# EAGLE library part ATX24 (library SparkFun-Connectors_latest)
ATX24 Pin Power Supply Connector - Right Angle PTH Mount This is a good connector for connecting a computer power supply to a PCB. It's massive, but provides many amps of power at 5V and 12V. SparkFun Products: SparkFun Benchtop Power Board Kit SparkFun Power Driver Shield Kit

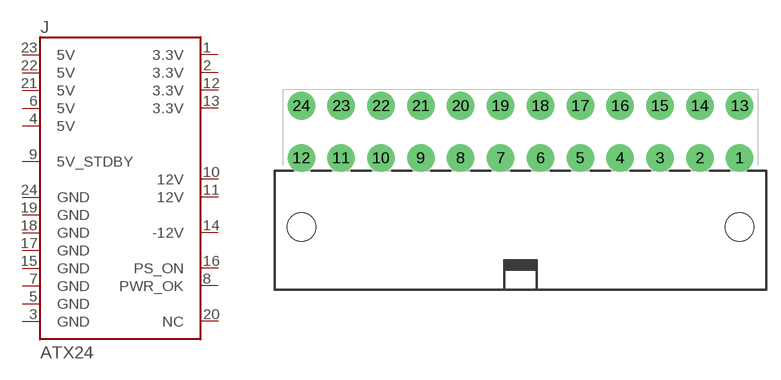
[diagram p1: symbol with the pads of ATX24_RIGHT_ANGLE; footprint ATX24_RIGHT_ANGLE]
Designator prefix J

## ATX24RH (PROD_ID: CONN-09674; SF_ID: PRT-09498)  [ATX24_RIGHT_ANGLE]
1  3.3V
2  3.3V
3  GND
4  5V
5  GND
6  5V
7  GND
8  PWR_OK
9  5V_STDBY
10  12V
11  12V
12  3.3V
13  3.3V
14  -12V
15  GND
16  PS_ON
17  GND
18  GND
19  GND
20  NC
21  5V
22  5V
23  5V
24  GND

## Footprint ATX24_RIGHT_ANGLE (pad centres in mm)
Molex Mini-Fit Jr. - 24 pin, Right Angle Specifications: Pin count:24 Datasheet referenced for footprint Example device(s): ATX24
drill 1.8 pad 2.9: 1 23.1,4.76; 2 18.9,4.76; 3 14.7,4.76; 4 10.5,4.76; 5 6.3,4.76; 6 2.1,4.76; 7 -2.1,4.76; 8 -6.3,4.76; 9 -10.5,4.76; 10 -14.7,4.76; 11 -18.9,4.76; 12 -23.1,4.76; 13 23.1,10.26; 14 18.9,10.26; 15 14.7,10.26; 16 10.5,10.26; 17 6.3,10.26; 18 2.1,10.26; 19 -2.1,10.26; 20 -6.3,10.26; 21 -10.5,10.26; 22 -14.7,10.26; 23 -18.9,10.26; 24 -23.1,10.26
hole 3 at -23.1,-2.54
hole 3 at 23.1,-2.54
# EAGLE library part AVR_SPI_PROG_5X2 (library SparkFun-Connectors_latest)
AVR 10-pin ICSP Header This is the standard AVR In Circuit Serial Programming header. Minimal, but includes pin one indicator. Works with standard Olimex programmers. SparkFun Products: 2x5 AVR ICSP Male Header - PTH 2x5 Pin Shrouded Header - PTH2

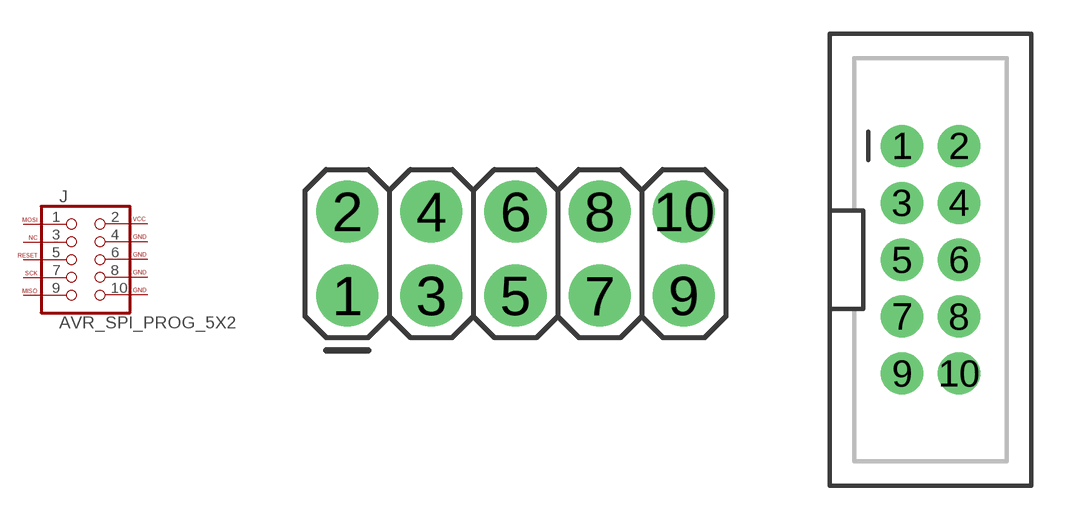
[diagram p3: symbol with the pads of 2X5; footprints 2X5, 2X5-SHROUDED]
Designator prefix J

## AVR_SPI_PROG_5X2PTH  [2X5]
1  MOSI  pas
2  VCC  pwr
3  NC  nc
4  GND  pwr
5  RESET  pas
6  GND  pwr
7  SCK  pas
8  GND  pwr
9  MISO  pas
10  GND  pwr

## AVR_SPI_PROG_5X2PTH2 (PROD_ID: CONN-08671; SF_ID: PRT-08506)  [2X5-SHROUDED]
Pads as for 2X5

## AVR_SPI_PROG_5X2LOCK (PROD_ID: CONN-08671; SF_ID: PRT-08506)  [2X5-SHROUDED_LOCK]
Pads as for 2X5

## AVR_SPI_PROG_5X2SMD  [2X5-SHROUDED_SMD]
Pads as for 2X5

## Footprint 2X5 (pad centres in mm)
Plated Through Hole - 2x5 Specifications: Pin count:10 Pin pitch:0.1" Example device(s): CONN_05x2
drill 1.016 pad 1.88: 1 0,0; 2 0,2.54; 3 2.54,0; 4 2.54,2.54; 5 5.08,0; 6 5.08,2.54; 7 7.62,0; 8 7.62,2.54; 9 10.16,0; 10 10.16,2.54

## Footprint 2X5-SHROUDED (pad centres in mm)
Plated Through Hole - 2x5 Shrouded Header Specifications: Pin count:10 Pin pitch:0.1" Datasheet referenced for footprint Example device(s): CONN_05x2
drill 1.016 pad 1.88: 1 -1.27,5.08; 2 1.27,5.08; 3 -1.27,2.54; 4 1.27,2.54; 5 -1.27,0; 6 1.27,0; 7 -1.27,-2.54; 8 1.27,-2.54; 9 -1.27,-5.08; 10 1.27,-5.08

## Footprint 2X5-SHROUDED_LOCK (pad centres in mm)
Plated Through Hole - 2x5 Shrouded Header Locking Footprint Holes are offset 0.005" from center, to hold pins in place during soldering. Specifications: Pin count:10 Pin pitch:0.1" Datasheet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
drill 1.016 pad 1.88: 1 -1.397,5.08; 2 1.397,5.08; 3 -1.397,2.54; 4 1.397,2.54; 5 -1.397,0; 6 1.397,0; 7 -1.397,-2.54; 8 1.397,-2.54; 9 -1.397,-5.08; 10 1.397,-5.08

## Footprint 2X5-SHROUDED_SMD (pad centres in mm)
Surface Mount - 2x5 Shrouded Header Specifications: Pin count:10 Pin pitch:0.1" Datasheet referenced for footprint Example device(s): CONN_05x2
smd 4.15 x 1: 1 -2.794,5.08; 2 2.794,5.08; 3 -2.794,2.54; 4 2.794,2.54; 5 -2.794,0; 6 2.794,0; 7 -2.794,-2.54; 8 2.794,-2.54; 9 -2.794,-5.08; 10 2.794,-5.08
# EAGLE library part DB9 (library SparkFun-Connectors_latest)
DB9 Connector Standard DB9 (D-Sub 9) serial connector. Can be used for CAN bus as well as RS485 and RS232. Footprint production proven. Here is the female version connector we sell at SparkFun: 9 Pin Female Serial Connector - PCB Mount (PRT-00429) This connector has been used on the following SparkFun products: SparkFun RS232 Shifter - SMD (PRT-00449) SparkFun RS232 Shifter SMD (No DB9) (PRT-08780)

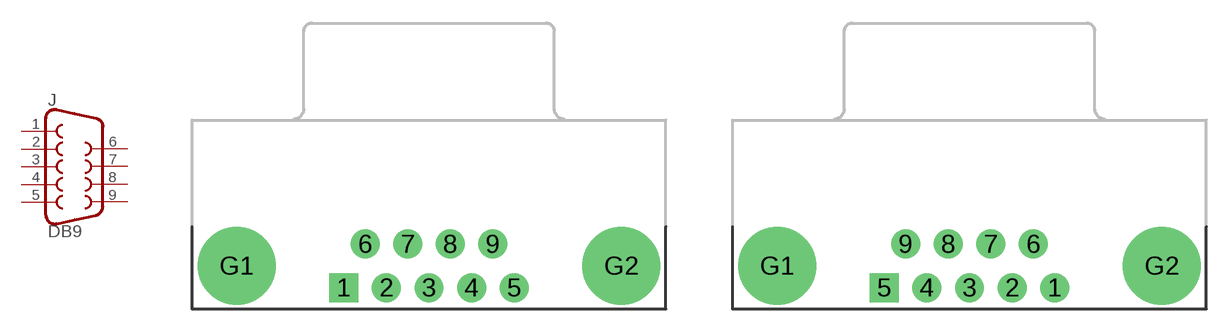
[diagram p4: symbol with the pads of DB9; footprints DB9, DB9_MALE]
Designator prefix J

## DB9FEMALE (PROD_ID: CONN-08194)  [DB9]
1  1  pas
2  2  pas
3  3  pas
4  4  pas
5  5  pas
6  6  pas
7  7  pas
8  8  pas
9  9  pas

## DB9MALE (PROD_ID: CONN-09904)  [DB9_MALE]
Pads as for DB9

## Footprint DB9 (pad centres in mm)
9 Pin Serial Connector - Female PCB Mount Right Angle 0.318" style. Specifications: Pin count:11 Datasheet referenced for footprint Example device(s): DB9
drill 1.016 pad 1.88 square: 1 -5.54,-1.42
drill 1.016 pad 1.88: 2 -2.77,-1.42; 3 0,-1.42; 4 2.77,-1.42; 5 5.54,-1.42; 6 -4.15,1.42; 7 -1.38,1.42; 8 1.38,1.42; 9 4.15,1.42
drill 3.302 pad 5.08: G1 -12.5,0; G2 12.5,0

## Footprint DB9_MALE (pad centres in mm)
9 Pin Serial Connector - Male PCB Mount Right Angle 0.318" style. Specifications: Pin count:11 Datasheet referenced for footprint Example device(s): DB9
drill 1.016 pad 1.88: 1 5.54,-1.42; 2 2.77,-1.42; 3 0,-1.42; 4 -2.77,-1.42; 6 4.15,1.42; 7 1.38,1.42; 8 -1.38,1.42; 9 -4.15,1.42
drill 1.016 pad 1.88 square: 5 -5.54,-1.42
drill 3.302 pad 5.08: G1 -12.5,0; G2 12.5,0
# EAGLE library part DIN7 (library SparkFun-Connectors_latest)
Mini-DIN7 Connector Through-hole MiniDIN 7 connector. Commonly used with Roomba products. Don't confuse this with DIN-6, which is commonly used on oldschool keyboards and mice. Here is the female version connector we sell at SparkFun: MiniDIN 7-Pin Connector (PRT-00696)

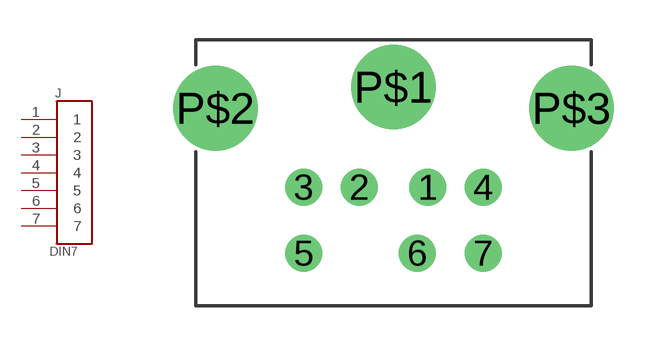
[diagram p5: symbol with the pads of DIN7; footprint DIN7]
Designator prefix J

## DIN7 (PROD_ID: CONN-08318; SF_ID: PRT-00696)  [DIN7]
1  1
2  2
3  3
4  4
5  5
6  6
7  7

## Footprint DIN7 (pad centres in mm)
miniDIN Right Angle Specifications: Pin count:7 Datasheet referenced for footprint Example device(s): DIN7
drill 0.9: 1 1.3,-3.8; 2 -1.3,-3.8; 3 -3.4,-3.8; 4 3.4,-3.8; 5 -3.4,-6.3; 6 0.9,-6.3; 7 3.4,-6.3
drill 2.2: P$1 0,0; P$2 -6.75,-0.8; P$3 6.75,-0.8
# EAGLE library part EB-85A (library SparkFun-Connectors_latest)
EB-85A Connector Horizontal surface mount connector for the EB-85A/FV-M8 GPS receiver. Here is the connector we sell at SparkFun: Connector Horizontal SMD for EB-85A (GPS-08297) Datasheet It was also used on this SparkFun product: This connector is not on any currently live products, however it has been used on previously reitred products, so the package is proven.

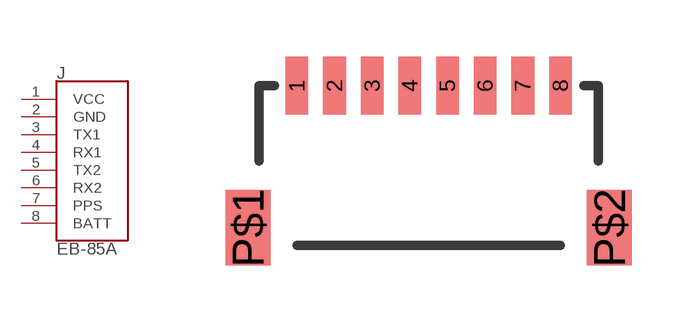
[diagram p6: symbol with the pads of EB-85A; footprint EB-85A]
Designator prefix J

## EB-85ASMD (PROD_ID: CONN-08435; SF_ID: GPS-08297)  [EB-85A]
1  VCC  pwr
2  GND  pwr
3  TX1  out
4  RX1  in
5  TX2  out
6  RX2  in
7  PPS  out
8  BATT  pwr

## Footprint EB-85A (pad centres in mm)
EB-85A Connector Horizontal surface mount connector for the EB-85A/FV-M8 GPS receiver. Specifications: Pin count: 10 Datasheet referenced for footprint Example device(s): EB-85A
smd 0.6 x 1.55: 1 0,0; 2 1,0; 3 2,0; 4 3,0; 5 4,0; 6 5,0; 7 6,0; 8 7,0
smd 1.2 x 2: P$1 -1.3,-3.775; P$2 8.3,-3.775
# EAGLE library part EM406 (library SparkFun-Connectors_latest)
EM406 GPS Connector Here is a six pin vertical 1.0mm pitch connector. It is useful if you need something very tiny as a connection. These are not the standard JST type connectors we use on most of our boards, but are actually the much smaller JST-SH type. Here is the connector we sell at SparkFun: JST SH Vertical 6-Pin Connector - SMD (GPS-00579) Datasheet It was used on these SparkFun products: SparkFun GPS Breakout (BOB-11818) SparkFun Weather Shield (DEV-12081) And many, many other GPS related products.

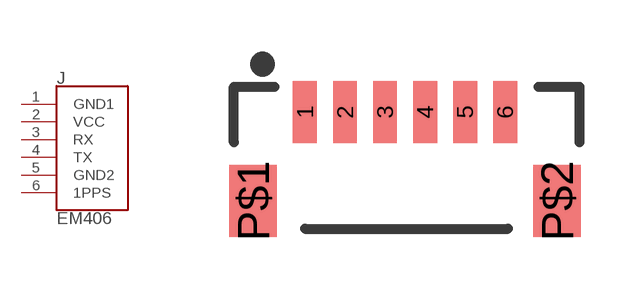
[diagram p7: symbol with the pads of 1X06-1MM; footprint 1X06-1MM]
Designator prefix J

## EM406 (PROD_ID: CONN-08249; SF_ID: GPS-00579)  [1X06-1MM]
1  GND1
2  VCC
3  RX
4  TX
5  GND2
6  1PPS

## Footprint 1X06-1MM (pad centres in mm)
JST SH Vertical 6-Pin Connector -SMD Specifications: Pin count:6 Pin pitch:1mm Datasheet referenced for footprint Example device(s): CONN_06 EM-406
smd 0.6 x 1.55: 1 -2.54,1.27; 2 -1.54,1.27; 3 -0.54,1.27; 4 0.46,1.27; 5 1.46,1.27; 6 2.46,1.27
smd 1.2 x 1.8: P$1 -3.84,-0.955; P$2 3.76,-0.955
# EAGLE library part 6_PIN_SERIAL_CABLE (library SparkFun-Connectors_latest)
6-pin header connection for use with the "FTDI BASIC" pinout - CABLE SIDE. Also known as "Arduino Serial Program Header". This is used on a design to provide a 6-pin connection point for serial communication usually from a USB cable (D+/D-) to these headers (RX/TX). It also has the remaining pins necessary for programming in the Arduino evironment (DTR, GND, and sometimes VCC). Note, this device has "CABLE" in the name. It is intended to be used on a design that usually lives on the end of your USB cable and prvides the converter chip (FTDI232 or FTDI231x) to commnicate serial RX/TX. The "sister" device, named "TARGET" is inteneded to be used on a design that contains a target micro-controller that you wish to program. You can populate with some of these: Female Headers (PRT-00115) For reference (or to suit your programming needs) check out these designs: SparkFun FTDI Basic Breakout - 5V (DEV-09716) SparkFun FTDI Basic Breakout - 3.3V (DEV-09873) SparkFun FTDI SmartBasic (DEV-12935) SparkFun Beefy 3 - FTDI Basic Breakout (DEV-13746)

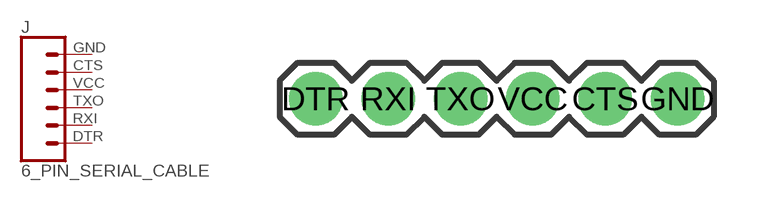
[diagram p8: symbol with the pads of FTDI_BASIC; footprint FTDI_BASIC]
Designator prefix J

## 6_PIN_SERIAL_CABLEPTH  [FTDI_BASIC]
CTS  5  pas
DTR  1  pas
GND  6  pas
RXI  2  pas
TXO  3  pas
VCC  4  pas

## Footprint FTDI_BASIC (pad centres in mm)
FTDI Basic Includes tDocu labels for end pins that match the FTDI Basic connection. Specifications: Pin count: 6 Pin pitch: 0.1" Example device(s): 6_Pin_Serial_Cable
drill 1.016 pad 1.88: CTS 10.16,0; DTR 0,0; GND 12.7,0; RXI 2.54,0; TXO 5.08,0; VCC 7.62,0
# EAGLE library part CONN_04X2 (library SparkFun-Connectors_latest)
Multi connection point. Often used as Generic Header-pin footprint for 0.1 inch spaced/style header connections On any of the 0.1 inch spaced packages, you can populate with these: Break Away Headers - Straight (PRT-00116) Break Away Male Headers - Right Angle (PRT-00553) Female Headers (PRT-00115) Break Away Headers - Machine Pin (PRT-00117) Break Away Female Headers - Swiss Machine Pin (PRT-00743)

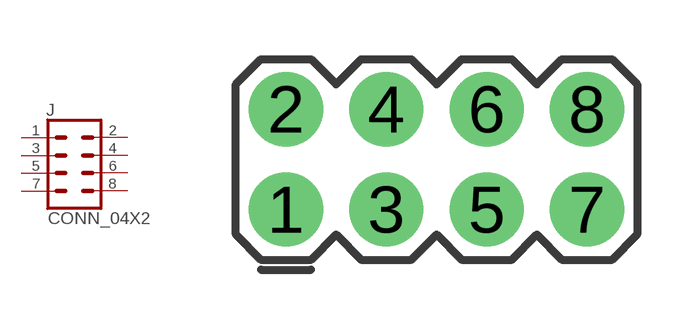
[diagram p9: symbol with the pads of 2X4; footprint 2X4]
Designator prefix J

## CONN_04X2  [2X4]
1  1  pas
2  2  pas
3  3  pas
4  4  pas
5  5  pas
6  6  pas
7  7  pas
8  8  pas

## Footprint 2X4 (pad centres in mm)
Plated Through Hole - 2x4 Specifications: Pin count:8 Pin pitch:0.1" Example device(s): CONN_04x2
drill 1.016 pad 1.88: 1 -3.81,-1.27; 2 -3.81,1.27; 3 -1.27,-1.27; 4 -1.27,1.27; 5 1.27,-1.27; 6 1.27,1.27; 7 3.81,-1.27; 8 3.81,1.27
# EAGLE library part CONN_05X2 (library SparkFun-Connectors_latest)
Multi connection point. Often used as Generic Header-pin footprint for 0.1 inch spaced/style header connections For AVR SPI programming port, see special device with nice symbol: "AVR_SPI_PROG_5x2.dev" You can populate with any combo of single row headers, but if you'd like an exact match, check these: 2x5 AVR ICSP Male Header (PRT-00778) 2x5 Pin Shrouded Header (PRT-08506) On any of the 0.1 inch spaced packages, you can populate with these: Break Away Headers - Straight (PRT-00116) Break Away Male Headers - Right Angle (PRT-00553) Female Headers (PRT-00115) Break Away Headers - Machine Pin (PRT-00117) Break Away Female Headers - Swiss Machine Pin (PRT-00743) Special note: the shrouded connector mates well with our 5x2 ribbon cables: 2x5 Pin IDC Ribbon Cable (PRT-08535)

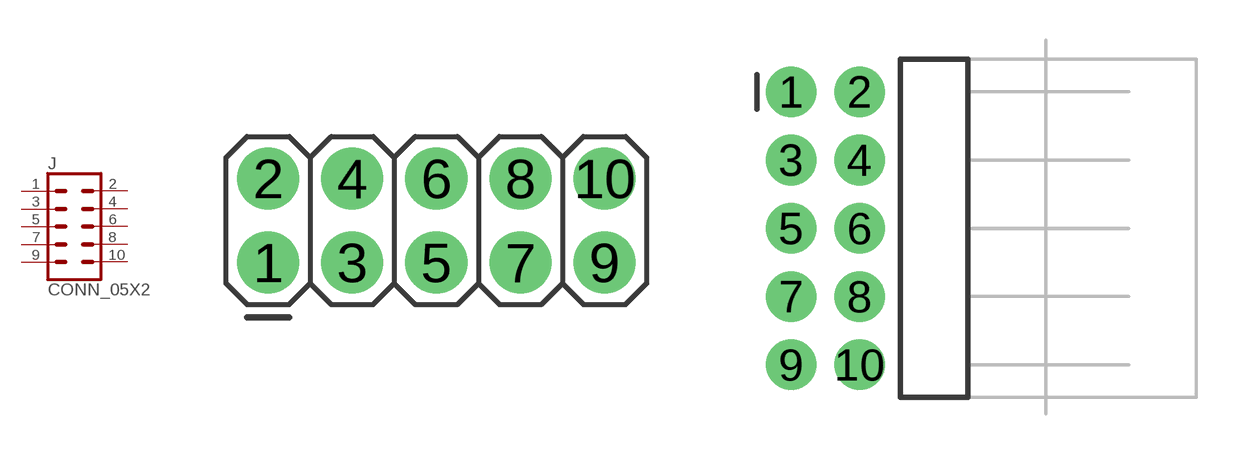
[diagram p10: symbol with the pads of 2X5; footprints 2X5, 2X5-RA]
Designator prefix J

## CONN_05X2PTH (PROD_ID: CONN-08499; SF_ID: PRT-0778)  [2X5]
1  1  pas
2  2  pas
3  3  pas
4  4  pas
5  5  pas
6  6  pas
7  7  pas
8  8  pas
9  9  pas
10  10  pas

## CONN_05X2RA  [2X5-RA]
Pads as for 2X5

## CONN_05X2RAF  [2X5-RAF]
Pads as for 2X5

## CONN_05X2SHD (PROD_ID: CONN-08671; SF_ID: PRT-08506)  [2X5-SHROUDED]
Pads as for 2X5

## CONN_05X2SHD_LOCK (PROD_ID: CONN-08671; SF_ID: PRT-08506)  [2X5-SHROUDED_LOCK]
Pads as for 2X5

## CONN_05X2SHD_SMD (PROD_ID: CONN-09508)  [2X5-SHROUDED_SMD]
Pads as for 2X5

## CONN_05X2NO_SILK  [2X5_NOSILK]
Pads as for 2X5

## CONN_05X20.05_IN_PTH_SILK  [2X5_PTH_SILK_.05]
Pads as for 2X5

## CONN_05X2SHD-NS (PROD_ID: CONN-08671; SF_ID: PRT-08506)  [2X5-SHROUDED-NS]
Pads as for 2X5

## Footprint 2X5 (pad centres in mm)
Plated Through Hole - 2x5 Specifications: Pin count:10 Pin pitch:0.1" Example device(s): CONN_05x2
drill 1.016 pad 1.88: 1 0,0; 2 0,2.54; 3 2.54,0; 4 2.54,2.54; 5 5.08,0; 6 5.08,2.54; 7 7.62,0; 8 7.62,2.54; 9 10.16,0; 10 10.16,2.54

## Footprint 2X5-RA (pad centres in mm)
Plated Through Hole - 2x5 Right Angle Male Headers tDocu shows pin location. Specifications: Pin count:10 Pin pitch:0.1" Example device(s): CONN_05x2
drill 1.016 pad 1.88: 1 -1.27,5.08; 2 1.27,5.08; 3 -1.27,2.54; 4 1.27,2.54; 5 -1.27,0; 6 1.27,0; 7 -1.27,-2.54; 8 1.27,-2.54; 9 -1.27,-5.08; 10 1.27,-5.08

## Footprint 2X5-RAF (pad centres in mm)
Plated Through Hole - 2x5 Right Angle Female Header Silk outline of pins Specifications: Pin count:10 Pin pitch:0.1" Example device(s): CONN_05x2
drill 1.016 pad 1.88: 1 -1.27,5.08; 2 1.27,5.08; 3 -1.27,2.54; 4 1.27,2.54; 5 -1.27,0; 6 1.27,0; 7 -1.27,-2.54; 8 1.27,-2.54; 9 -1.27,-5.08; 10 1.27,-5.08

## Footprint 2X5-SHROUDED (pad centres in mm)
Plated Through Hole - 2x5 Shrouded Header Specifications: Pin count:10 Pin pitch:0.1" Datasheet referenced for footprint Example device(s): CONN_05x2
drill 1.016 pad 1.88: 1 -1.27,5.08; 2 1.27,5.08; 3 -1.27,2.54; 4 1.27,2.54; 5 -1.27,0; 6 1.27,0; 7 -1.27,-2.54; 8 1.27,-2.54; 9 -1.27,-5.08; 10 1.27,-5.08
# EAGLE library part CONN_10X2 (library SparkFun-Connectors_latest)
Multi connection point. Often used as Generic Header-pin footprint for 0.1 inch spaced/style header connections On any of the 0.1 inch spaced packages, you can populate with these: Break Away Headers - Straight (PRT-00116) Break Away Male Headers - Right Angle (PRT-00553) Female Headers (PRT-00115) Break Away Headers - Machine Pin (PRT-00117) Break Away Female Headers - Swiss Machine Pin (PRT-00743) Special note about the "SPECIAL" package: This was SPECIALLY designed to be used with our Graphic LCD Backpack. Be sure you want to use this! It is not only staggered on each line of header holes, but IT IS ALSO offset of the center point of the top and bottom lines by 5 mil. This causes the headers to lock into place on the "standard" footprint on the LCD screen. The extra squares on the tdocu layer are there simply to reference other pins (if you were to actually populate a longer header than ten long - this is what we do with the backpacks).

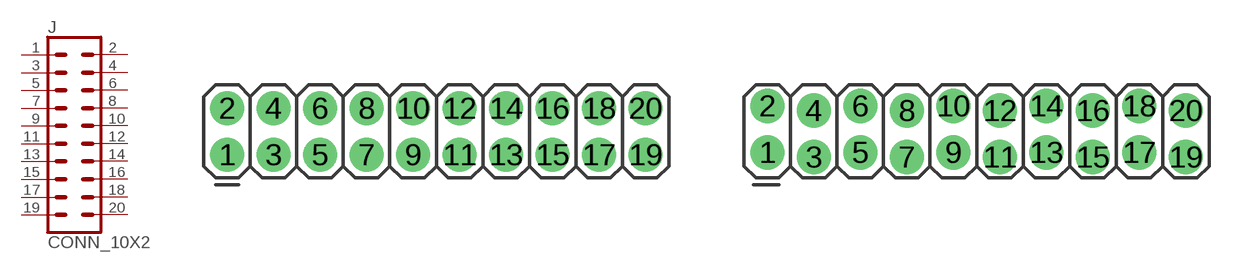
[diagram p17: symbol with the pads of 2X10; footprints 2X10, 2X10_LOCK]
Designator prefix J

## CONN_10X2  [2X10]
1  1  pas
2  2  pas
3  3  pas
4  4  pas
5  5  pas
6  6  pas
7  7  pas
8  8  pas
9  9  pas
10  10  pas
11  11  pas
12  12  pas
13  13  pas
14  14  pas
15  15  pas
16  16  pas
17  17  pas
18  18  pas
19  19  pas
20  20  pas

## CONN_10X22X10_LOCK  [2X10_LOCK]
Pads as for 2X10

## CONN_10X2SPECIAL  [2X10_LOCK_SPECIAL]
Pads as for 2X10

## CONN_10X2NOSILK  [2X10_NOSILK]
Pads as for 2X10

## Footprint 2X10 (pad centres in mm)
Plated Through Hole - 2x10 Specifications: Pin count:20 Pin pitch:0.1" Example device(s): CONN_10x2
drill 1.016 pad 1.88: 1 0,0; 2 0,2.54; 3 2.54,0; 4 2.54,2.54; 5 5.08,0; 6 5.08,2.54; 7 7.62,0; 8 7.62,2.54; 9 10.16,0; 10 10.16,2.54; 11 12.7,0; 12 12.7,2.54; 13 15.24,0; 14 15.24,2.54; 15 17.78,0; 16 17.78,2.54; 17 20.32,0; 18 20.32,2.54; 19 22.86,0; 20 22.86,2.54

## Footprint 2X10_LOCK (pad centres in mm)
Plated Through Hole - 2x10 Locking Footprint Holes are offset 0.005", to hold pins in place while soldering. Specifications: Pin count:20 Pin pitch:0.1" Example device(s): CONN_10x2
drill 1.016 pad 1.88: 1 0,0.127; 2 0,2.667; 3 2.54,-0.127; 4 2.54,2.413; 5 5.08,0.127; 6 5.08,2.667; 7 7.62,-0.127; 8 7.62,2.413; 9 10.16,0.127; 10 10.16,2.667; 11 12.7,-0.127; 12 12.7,2.413; 13 15.24,0.127; 14 15.24,2.667; 15 17.78,-0.127; 16 17.78,2.413; 17 20.32,0.127; 18 20.32,2.667; 19 22.86,-0.127; 20 22.86,2.413

## Footprint 2X10_LOCK_SPECIAL (pad centres in mm)
Plated Through Hole - 2x10 Locking Footprint Special Holes are offset 0.005", to hold pins in place while soldering. Pin rows are offset 5mm as well Specifications: Pin count:20 Pin pitch:0.1"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
drill 1.016 pad 1.88: 1 0,-0.152; 2 0,2.946; 3 2.54,-0.406; 4 2.54,2.692; 5 5.08,-0.152; 6 5.08,2.946; 7 7.62,-0.406; 8 7.62,2.692; 9 10.16,-0.152; 10 10.16,2.946; 11 12.7,-0.406; 12 12.7,2.692; 13 15.24,-0.152; 14 15.24,2.946; 15 17.78,-0.406; 16 17.78,2.692; 17 20.32,-0.152; 18 20.32,2.946; 19 22.86,-0.406; 20 22.86,2.692

## Footprint 2X10_NOSILK (pad centres in mm)
Plated Through Hole - 2x10 No Silk Outline Specifications: Pin count:20 Pin pitch:0.1" Example device(s): CONN_10x2
drill 1.016 pad 1.88: 1 0,0; 2 0,2.54; 3 2.54,0; 4 2.54,2.54; 5 5.08,0; 6 5.08,2.54; 7 7.62,0; 8 7.62,2.54; 9 10.16,0; 10 10.16,2.54; 11 12.7,0; 12 12.7,2.54; 13 15.24,0; 14 15.24,2.54; 15 17.78,0; 16 17.78,2.54; 17 20.32,0; 18 20.32,2.54; 19 22.86,0; 20 22.86,2.54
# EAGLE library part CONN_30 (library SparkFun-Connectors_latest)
Multi connection point. Often used as Generic Header-pin footprint for 0.1 inch spaced/style header connections On any of the 0.1 inch spaced packages, you can populate with these: Break Away Headers - Straight (PRT-00116) Break Away Male Headers - Right Angle (PRT-00553) Female Headers (PRT-00115) Break Away Headers - Machine Pin (PRT-00117) Break Away Female Headers - Swiss Machine Pin (PRT-00743) For SCREWTERMINALS and SPRING TERMINALS visit here: Screw Terimnals on SparkFun.com (5mm/3.5mm/2.54mm spacing) This device is also useful as a general connection point to wire up your design to another part of your project. Our various solder wires solder well into these plated through hole pads. Hook-Up Wire - Assortment (Stranded, 22 AWG) (PRT-11375) Hook-Up Wire - Assortment (Solid Core, 22 AWG) (PRT-11367) View the entire wire category on our website here Special notes: Molex polarized connector foot print use with SKU : PRT-08231 with associated crimp pins and housings. 1MM SMD Version SKU: PRT-10208 NOTES ON THE VARIANTS LOCK and LOCK_LONGPADS... This footprint was designed to help hold the alignment of a through-hole component (i.e. 6-pin header) while soldering it into place. You may notice that each hole has been shifted either up or down by 0.005 of an inch from it's more standard position (which is a perfectly straight line). This slight alteration caused the pins (the squares in the middle) to touch the edges of the holes. Because they are alternating, it causes a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

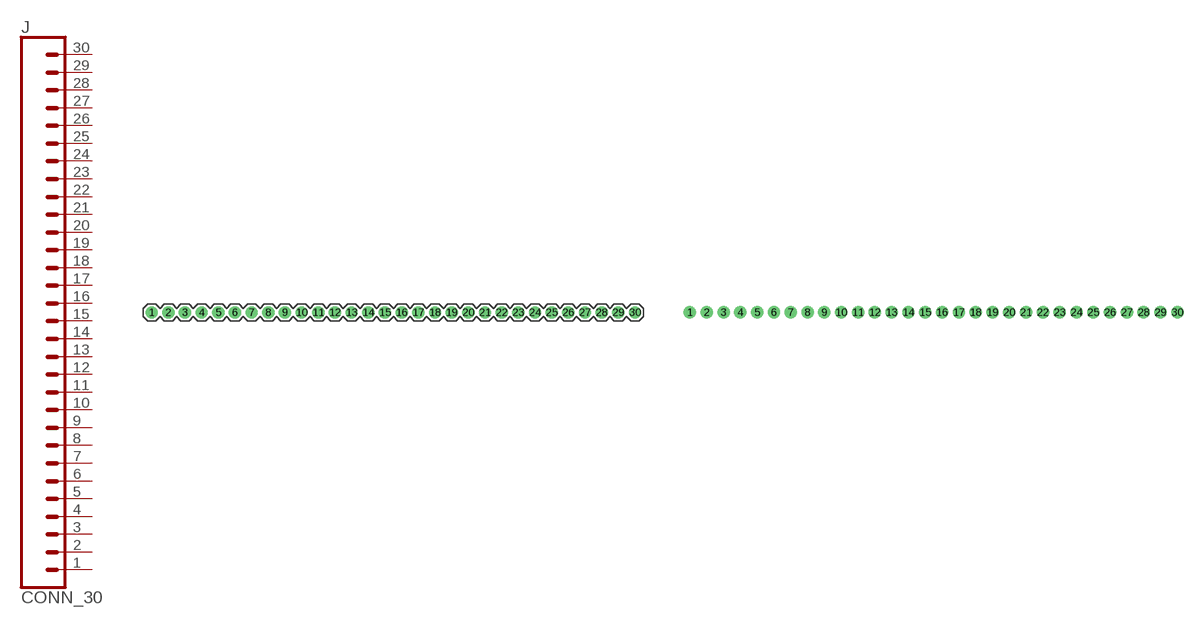
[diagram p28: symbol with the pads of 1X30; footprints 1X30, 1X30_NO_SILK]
Designator prefix J

## CONN_30  [1X30]
1  1  pas
2  2  pas
3  3  pas
4  4  pas
5  5  pas
6  6  pas
7  7  pas
8  8  pas
9  9  pas
10  10  pas
11  11  pas
12  12  pas
13  13  pas
14  14  pas
15  15  pas
16  16  pas
17  17  pas
18  18  pas
19  19  pas
20  20  pas
21  21  pas
22  22  pas
23  23  pas
24  24  pas
25  25  pas
26  26  pas
27  27  pas
28  28  pas
29  29  pas
30  30  pas

## CONN_30NO_SILK  [1X30_NO_SILK]
Pads as for 1X30

## Footprint 1X30 (pad centres in mm)
Plated Through Hole -30 Pins Specifications: Pin count:30 Pin pitch:0.1" Example device(s): CONN_30
drill 1.016 pad 1.88: 1 0,0; 2 2.54,0; 3 5.08,0; 4 7.62,0; 5 10.16,0; 6 12.7,0; 7 15.24,0; 8 17.78,0; 9 20.32,0; 10 22.86,0; 11 25.4,0; 12 27.94,0; 13 30.48,0; 14 33.02,0; 15 35.56,0; 16 38.1,0; 17 40.64,0; 18 43.18,0; 19 45.72,0; 20 48.26,0; 21 50.8,0; 22 53.34,0; 23 55.88,0; 24 58.42,0; 25 60.96,0; 26 63.5,0; 27 66.04,0; 28 68.58,0; 29 71.12,0; 30 73.66,0

## Footprint 1X30_NO_SILK (pad centres in mm)
Plated Through Hole -30 Pins No Silk Outline Specifications: Pin count:30 Pin pitch:0.1" Example device(s): CONN_30
drill 1.016 pad 1.88: 1 0,0; 2 2.54,0; 3 5.08,0; 4 7.62,0; 5 10.16,0; 6 12.7,0; 7 15.24,0; 8 17.78,0; 9 20.32,0; 10 22.86,0; 11 25.4,0; 12 27.94,0; 13 30.48,0; 14 33.02,0; 15 35.56,0; 16 38.1,0; 17 40.64,0; 18 43.18,0; 19 45.72,0; 20 48.26,0; 21 50.8,0; 22 53.34,0; 23 55.88,0; 24 58.42,0; 25 60.96,0; 26 63.5,0; 27 66.04,0; 28 68.58,0; 29 71.12,0; 30 73.66,0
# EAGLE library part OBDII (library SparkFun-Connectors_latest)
OBD-II Connector OBDII is an on board diagnostics standard that is used on a large variety of cars. Here is the connector we sell at SparkFun: OBD-II connector (DEV-09911) Info and Pinout (sorry, no datasheet) We do not use this connector on any active designs, however, if you're looking for OBDII tech, please check out these: SparkFun OBD related products

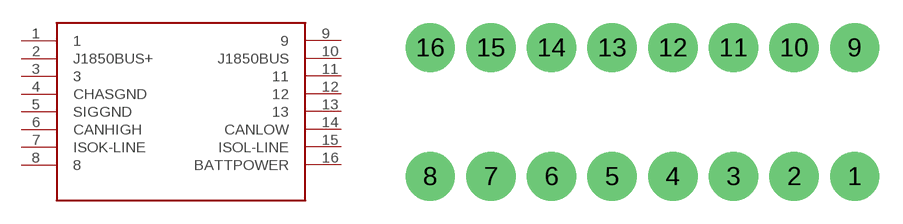
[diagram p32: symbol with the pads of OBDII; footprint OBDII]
Designator prefix J

## OBDII (SF_ID: DEV-09911)  [OBDII]
1  1
2  J1850BUS+
3  3
4  CHASGND
5  SIGGND
6  CANHIGH
7  ISOK-LINE
8  8
9  9
10  J1850BUS
11  11
12  12
13  13
14  CANLOW
15  ISOL-LINE
16  BATTPOWER

## Footprint OBDII (pad centres in mm)
OBD-II Automotive Connector Specifications: Pin count: 16 Pin pitch:0.15" Example device(s): OBD-II
drill 2.2: 1 13.68,-3.81; 2 9.73,-3.81; 3 5.78,-3.81; 4 1.83,-3.81; 5 -2.12,-3.81; 6 -6.07,-3.81; 7 -10.02,-3.81; 8 -13.97,-3.81; 9 13.68,4.59; 10 9.73,4.59; 11 5.78,4.59; 12 1.83,4.59; 13 -2.12,4.59; 14 -6.07,4.59; 15 -10.02,4.59; 16 -13.97,4.59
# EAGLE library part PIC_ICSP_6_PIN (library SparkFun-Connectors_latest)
ISCP Programming connector for PICs This 6 pin header contains all the lines necessary for programming most PIC microcontrollers. Here is the connector we sell at SparkFun: Polarized Connectors - Header (6-Pin) (PRT-08094) It is used on this SparkFun product: SparkFun UDB5 - PIC UAV Development Board (DEV-11703) Also, if you need a nice PIC programmer, please check these out: MPLAB PICkit 3 (PGM-09973)

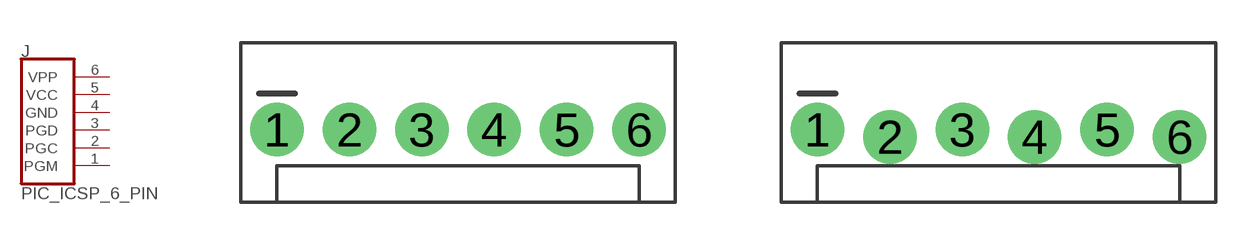
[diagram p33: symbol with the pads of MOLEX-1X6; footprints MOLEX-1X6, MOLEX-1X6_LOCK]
Designator prefix J

## PIC_ICSP_6_PIN (PROD_ID: CONN-08046; SF_ID: PRT-08094)  [MOLEX-1X6]
1  PGM
2  PGC
3  PGD
4  GND  pwr
5  VCC  pwr
6  VPP

## PIC_ICSP_6_PINPOLAR_LOCK  [MOLEX-1X6_LOCK]
Pads as for MOLEX-1X6

## Footprint MOLEX-1X6 (pad centres in mm)
Molex 6-Pin Plated Through-Hole Specifications: Pin count:6 Pin pitch:0.1" Datasheet referenced for footprint Example device(s): CONN_06
drill 1.016 pad 1.88: 1 0,0; 2 2.54,0; 3 5.08,0; 4 7.62,0; 5 10.16,0; 6 12.7,0

## Footprint MOLEX-1X6_LOCK (pad centres in mm)
Molex 6-Pin Plated Through-Hole Locking Footprint Holes are offset 0.005" from center to hold pins in place during soldering. Specifications: Pin count:6 Pin pitch:0.1" Datasheet referenced for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
drill 1.016 pad 1.88: 1 0,0; 2 2.54,-0.254; 3 5.08,0; 4 7.62,-0.254; 5 10.16,0; 6 12.7,-0.254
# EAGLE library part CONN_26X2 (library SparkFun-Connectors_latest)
Multi connection point. Often used as Generic Header-pin footprint for 0.1 inch spaced/style header connections On any of the 0.1 inch spaced packages, you can populate with these: Break Away Headers - Straight (PRT-00116) Break Away Male Headers - Right Angle (PRT-00553) Female Headers (PRT-00115) Break Away Headers - Machine Pin (PRT-00117) Break Away Female Headers - Swiss Machine Pin (PRT-00743)

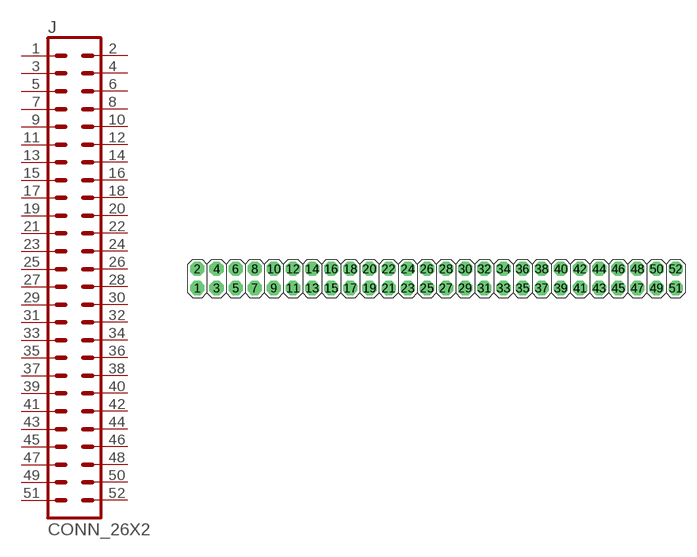
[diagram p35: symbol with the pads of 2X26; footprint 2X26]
Designator prefix J

## CONN_26X2  [2X26]
1  1  pas
2  2  pas
3  3  pas
4  4  pas
5  5  pas
6  6  pas
7  7  pas
8  8  pas
9  9  pas
10  10  pas
11  11  pas
12  12  pas
13  13  pas
14  14  pas
15  15  pas
16  16  pas
17  17  pas
18  18  pas
19  19  pas
20  20  pas
21  21  pas
22  22  pas
23  23  pas
24  24  pas
25  25  pas
26  26  pas
27  27  pas
28  28  pas
29  29  pas
30  30  pas
31  31  pas
32  32  pas
33  33  pas
34  34  pas
35  35  pas
36  36  pas
37  37  pas
38  38  pas
39  39  pas
40  40  pas
41  41  pas
42  42  pas
43  43  pas
44  44  pas
45  45  pas
46  46  pas
47  47  pas
48  48  pas
49  49  pas
50  50  pas
51  51  pas
52  52  pas

## Footprint 2X26 (pad centres in mm)
Plated Through Hole - 2x26 Specifications: Pin count:52 Pin pitch:0.1" Example device(s): CONN_26x2
drill 1.016 pad 1.88 octagon: 1 -11.43,-1.27; 2 -11.43,1.27; 3 -8.89,-1.27; 4 -8.89,1.27; 5 -6.35,-1.27; 6 -6.35,1.27; 7 -3.81,-1.27; 8 -3.81,1.27; 9 -1.27,-1.27; 10 -1.27,1.27; 11 1.27,-1.27; 12 1.27,1.27; 13 3.81,-1.27; 14 3.81,1.27; 15 6.35,-1.27; 16 6.35,1.27; 17 8.89,-1.27; 18 8.89,1.27; 19 11.43,-1.27; 20 11.43,1.27; 21 13.97,-1.27; 22 13.97,1.27; 23 16.51,-1.27; 24 16.51,1.27; 25 19.05,-1.27; 26 19.05,1.27; 27 21.59,-1.27; 28 21.59,1.27; 29 24.13,-1.27; 30 24.13,1.27; 31 26.67,-1.27; 32 26.67,1.27; 33 29.21,-1.27; 34 29.21,1.27; 35 31.75,-1.27; 36 31.75,1.27; 37 34.29,-1.27; 38 34.29,1.27; 39 36.83,-1.27; 40 36.83,1.27; 41 39.37,-1.27; 42 39.37,1.27; 43 41.91,-1.27; 44 41.91,1.27; 45 44.45,-1.27; 46 44.45,1.27; 47 46.99,-1.27; 48 46.99,1.27; 49 49.53,-1.27; 50 49.53,1.27; 51 52.07,-1.27; 52 52.07,1.27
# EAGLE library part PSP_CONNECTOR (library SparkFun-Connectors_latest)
Connector for the PlayStation Portable (PSP) screen ribbon cable We no longer sell the screens, however we do still sell the connector. Here is the connector we sell at SparkFun: Color 24-Bit LCD 4.3" PSP Connector (LCD-08355) Datasheet

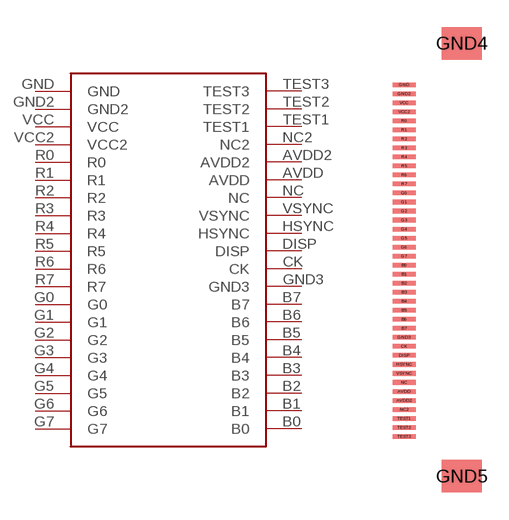
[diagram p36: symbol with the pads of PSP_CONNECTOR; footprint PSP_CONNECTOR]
Designator prefix J

## PSP_CONNECTOR (SF_ID: LCD-08355)  [PSP_CONNECTOR]
AVDD  AVDD
AVDD2  AVDD2
B0  B0
B1  B1
B2  B2
B3  B3
B4  B4
B5  B5
B6  B6
B7  B7
CK  CK
DISP  DISP
G0  G0
G1  G1
G2  G2
G3  G3
G4  G4
G5  G5
G6  G6
G7  G7
GND  GND
GND2  GND2
GND3  GND3
HSYNC  HSYNC
NC  NC
NC2  NC2
R0  R0
R1  R1
R2  R2
R3  R3
R4  R4
R5  R5
R6  R6
R7  R7
TEST1  TEST1
TEST2  TEST2
TEST3  TEST3
VCC  VCC
VCC2  VCC2
VSYNC  VSYNC

## Footprint PSP_CONNECTOR (pad centres in mm)
ZIF PSP Connector Specifications: Pin count: 42 Pin pitch:0.5mm Datasheet referenced for footprint Example device(s): PSP_CONNECTOR
smd 0.001 x 0.001 bottom: . 4.4,25.3
smd 1.27 x 0.254: AVDD 1,6; AVDD2 1,5.5; B0 1,13; B1 1,12.5; B2 1,12; B3 1,11.5; B4 1,11; B5 1,10.5; B6 1,10; B7 1,9.5; CK 1,8.5; DISP 1,8; G0 1,17; G1 1,16.5; G2 1,16; G3 1,15.5; G4 1,15; G5 1,14.5; G6 1,14; G7 1,13.5; GND 1,23; GND2 1,22.5; GND3 1,9; HSYNC 1,7.5; NC 1,6.5; NC2 1,5; R0 1,21; R1 1,20.5; R2 1,20; R3 1,19.5; R4 1,19; R5 1,18.5; R6 1,18; R7 1,17.5; TEST1 1,4.5; TEST2 1,4; TEST3 1,3.5; VCC 1,22; VCC2 1,21.5; VSYNC 1,7
smd 2.2 x 1.8: GND4 4.2,25.3; GND5 4.2,1.3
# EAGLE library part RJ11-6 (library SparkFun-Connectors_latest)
RJ11 Jack - 6 pin Commonly found on CAT3 devices and some Microchip programmers. Here is the connector we sell at SparkFun: RJ11 6-Pin Connector (PRT-00132) Datasheet It is used on this SparkFun product: SparkFun Weather Shield (DEV-12081) Weather Meters (SEN-08942)

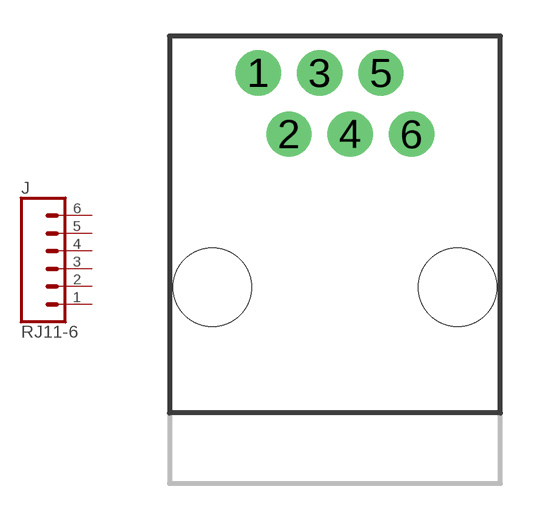
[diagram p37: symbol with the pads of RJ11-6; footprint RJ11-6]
Designator prefix J

## RJ11-6 (PROD_ID: CONN-08590; SF_ID: PRT-00132; VALUE: RJ11)  [RJ11-6]
1  1  pas
2  2  pas
3  3  pas
4  4  pas
5  5  pas
6  6  pas

## Footprint RJ11-6 (pad centres in mm)
RJ11 6-Pin Socket with PCB Mounting Post Specifications: Pin count: 6 Datasheet referenced for footprint Example device(s): RJ11-6
drill 1.016 pad 1.88: 1 -3.175,8.89; 2 -1.905,6.35; 3 -0.635,8.89; 4 0.635,6.35; 5 1.905,8.89; 6 3.175,6.35
hole 3.251 at -5.08,0
hole 3.251 at 5.08,0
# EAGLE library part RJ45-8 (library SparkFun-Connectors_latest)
RJ45 Jack - 8 pin Simple RJ45, 8-pin connection. Commonly used for Cat5, Cat5e, and Cat6 Ethernet cables. Here is the connector we sell at SparkFun: RJ45 8-Pin Connector (PRT-00643) Datasheet It is used on this SparkFun product: SparkFun RJ45 Breakout (BOB-00716) Note, you may also be interested in the "MAGJACK" version of this. It is basically a RJ45 connector, but also has some status LEDs built into the connector housing. You can check that out in this library at the device named "MAGJACK.dev" and see these products online: RJ45 Ethernet MagJack-Compatible (PRT-08534) SparkFun RJ45 MagJack Breakout (BOB-13021)

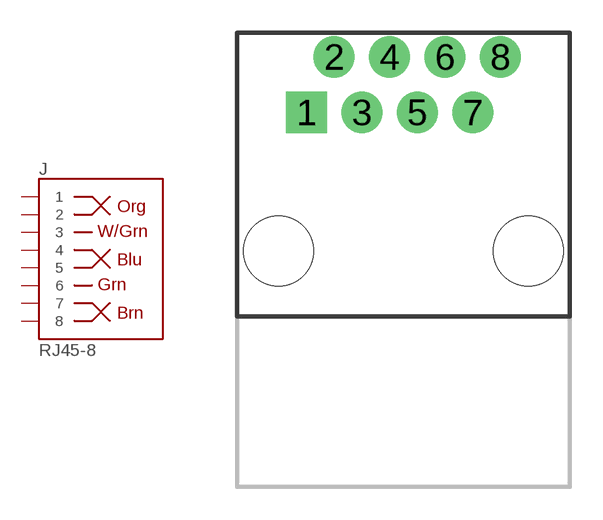
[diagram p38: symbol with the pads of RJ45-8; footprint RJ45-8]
Designator prefix J

## RJ45-8 (PROD_ID: CONN-08506; SF_ID: PRT-00643; VALUE: RJ45)  [RJ45-8]
1  1
2  2
3  3
4  4
5  5
6  6
7  7
8  8

## Footprint RJ45-8 (pad centres in mm)
RJ45 Socket with PCB Mounting Posts Specifications: Pin count:8 Datasheet referenced for footprint Example device(s): RJ45-8
drill 1 pad 1.88 square: 1 -4.445,6.35
drill 1 pad 1.88: 2 -3.175,8.89; 3 -1.905,6.35; 4 -0.635,8.89; 5 0.635,6.35; 6 1.905,8.89; 7 3.175,6.35; 8 4.445,8.89
hole 3.2 at -5.715,0
hole 3.2 at 5.715,0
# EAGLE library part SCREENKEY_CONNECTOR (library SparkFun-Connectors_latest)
Connector for the ScreenKey This is a tiny, locking 14-pin FPC/FFC connector that mates with the TFT ScreenKeys and their displays. These connectors require a really minimal amount of force to close, which is great for the delicate wires they’re designed for. Unfortunately, we no longer sell the ScreenKey TFT128 or the TFT128 Display, however we do still sell the connector. Here is the connector we sell at SparkFun: ScreenKey Mating Connector (PRT-09586) Datasheet (FH12-14S-0.5SH)

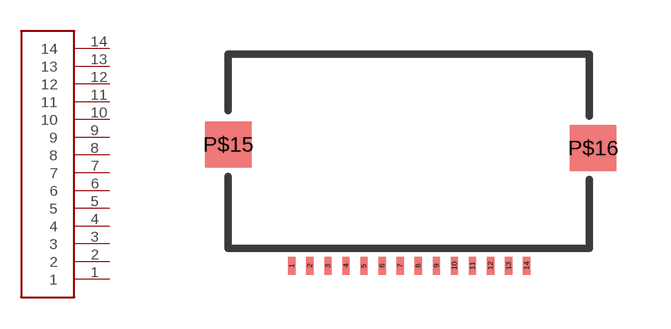
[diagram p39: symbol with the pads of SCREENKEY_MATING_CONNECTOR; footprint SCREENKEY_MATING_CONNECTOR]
Designator prefix J

## SCREENKEY_CONNECTOR (PROD_ID: CONN-09581; SF_ID: PRT-09586)  [SCREENKEY_MATING_CONNECTOR]
1  1
2  2
3  3
4  4
5  5
6  6
7  7
8  8
9  9
10  10
11  11
12  12
13  13
14  14

## Footprint SCREENKEY_MATING_CONNECTOR (pad centres in mm)
FPC/FFC Locking Connector - SMD Specifications: Pin count:14 Pin pitch: 0.5mm Datasheet referenced for footprint Example device(s): SCREENKEY_CONNECTOR
smd 0.2 x 0.5: 1 1.76,-0.36; 2 2.26,-0.36; 3 2.76,-0.36; 4 3.26,-0.36; 5 3.76,-0.36; 6 4.26,-0.36; 7 4.76,-0.36; 8 5.26,-0.36; 9 5.76,-0.36; 10 6.26,-0.36; 11 6.76,-0.36; 12 7.26,-0.36; 13 7.76,-0.36; 14 8.26,-0.36
smd 1.28 x 1.28: P$15 0,3; P$16 10.1,2.9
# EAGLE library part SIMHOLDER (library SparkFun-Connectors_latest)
SIM Cellular Card Socket SMT 6 pin standard connection. SparkFun Products: SIM Socket SparkFun Cellular Shield - MG2639 SparkFun SIM Card Socket Breakout

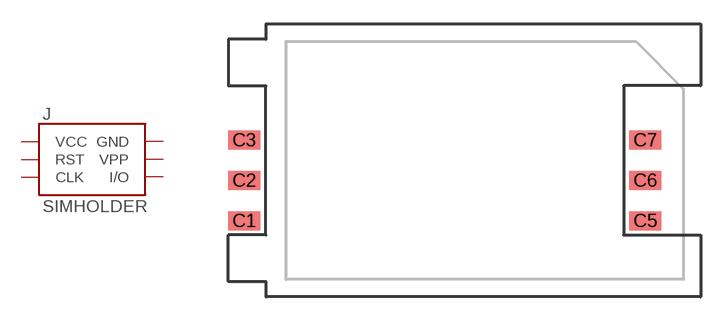
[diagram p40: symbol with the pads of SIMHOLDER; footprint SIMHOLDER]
Designator prefix J

## SIMHOLDERSIM (PROD_ID: CONN-08536; SF_ID: PRT-00548)  [SIMHOLDER]
C1  VCC  pwr
C2  RST  in
C3  CLK  in
C5  GND  pwr
C6  VPP  in
C7  I/O

## Footprint SIMHOLDER (pad centres in mm)
SIM Card Socket SMT Specifications: Pin count: 6 Pin pitch:2.54mm Datasheet referenced for footprint Example device(s): SIMHOLDER
smd 2 x 1.2: C1 -12.61,-3.81; C2 -12.61,-1.27; C3 -12.61,1.27; C5 12.61,-3.81; C6 12.61,-1.27; C7 12.61,1.27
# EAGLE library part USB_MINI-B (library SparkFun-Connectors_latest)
USB type Mini-B Connector Breaks out 5th pin, and includes shield pins if needed. SparkFun Products: SparkFun FTDI Basic Breakout SparkFun XBee Explorer USB SparkFun Redboard

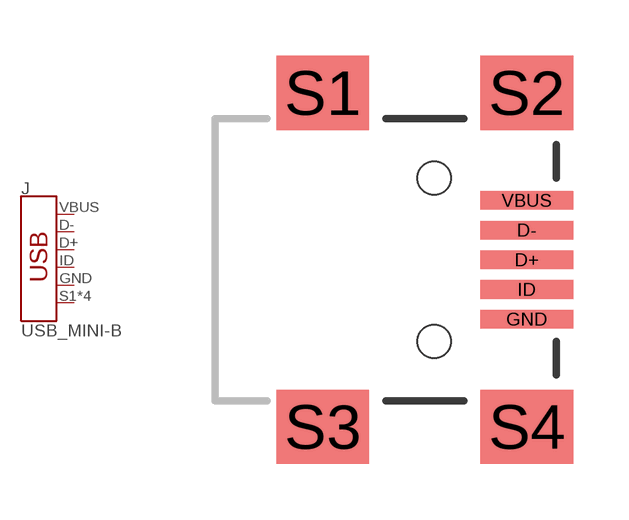
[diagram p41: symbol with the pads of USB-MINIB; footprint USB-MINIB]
Designator prefix J

## USB_MINI-B_SMT (PROD_ID: CONN-08193; SF_ID: PRT-00587)  [USB-MINIB]
D+  D+
D-  D-
GND  GND  pwr
ID  ID
S1  SHIELD
S2  SHIELD
S3  SHIELD
S4  SHIELD
VBUS  VBUS  pwr

## Footprint USB-MINIB (pad centres in mm)
USB Type Mini-B Surface Mounted Specifications: Pin count: 5 main, 4 shield pins Datasheet referenced for footprint Example device(s): USB_Mini-B
smd 2.5 x 0.5: D+ 2.5,0; D- 2.5,0.8; GND 2.5,-1.6; ID 2.5,-0.8; VBUS 2.5,1.6
smd 2.5 x 2: S1 -3,4.5; S2 2.5,4.5; S3 -3,-4.5; S4 2.5,-4.5
hole 0.9 at 0,2.2
hole 0.9 at 0,-2.2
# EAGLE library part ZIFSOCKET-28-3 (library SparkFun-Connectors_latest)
ZIF Socket 28-Pin 0.3" Lever-action ZIF socket for 28-pin ICs SparkFun Products: ZIF Socket 28-Pin

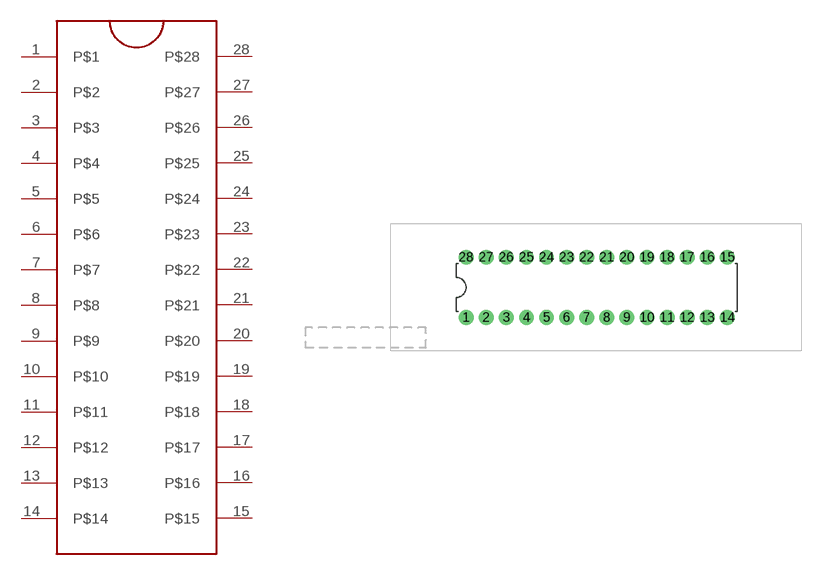
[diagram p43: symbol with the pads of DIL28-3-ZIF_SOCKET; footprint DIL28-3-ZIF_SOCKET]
Designator prefix J

## ZIFSOCKET-28-3" (PROD_ID: CONN-10960; SF_ID: PRT-09175)  [DIL28-3-ZIF_SOCKET]
1  P$1
2  P$2
3  P$3
4  P$4
5  P$5
6  P$6
7  P$7
8  P$8
9  P$9
10  P$10
11  P$11
12  P$12
13  P$13
14  P$14
15  P$15
16  P$16
17  P$17
18  P$18
19  P$19
20  P$20
21  P$21
22  P$22
23  P$23
24  P$24
25  P$25
26  P$26
27  P$27
28  P$28

## Footprint DIL28-3-ZIF_SOCKET (pad centres in mm)
ZIF Socket 28-Pin 0.3" tDocu shows location of lever when unlocked. Specifications: Pin count:28 Example device(s): ZIF_SOCKET_28-3
drill 1.016 pad 1.88: 1 -16.51,-3.81; 2 -13.97,-3.81; 3 -11.43,-3.81; 4 -8.89,-3.81; 5 -6.35,-3.81; 6 -3.81,-3.81; 7 -1.27,-3.81; 8 1.27,-3.81; 9 3.81,-3.81; 10 6.35,-3.81; 11 8.89,-3.81; 12 11.43,-3.81; 13 13.97,-3.81; 14 16.51,-3.81; 15 16.51,3.81; 16 13.97,3.81; 17 11.43,3.81; 18 8.89,3.81; 19 6.35,3.81; 20 3.81,3.81; 21 1.27,3.81; 22 -1.27,3.81; 23 -3.81,3.81; 24 -6.35,3.81; 25 -8.89,3.81; 26 -11.43,3.81; 27 -13.97,3.81; 28 -16.51,3.81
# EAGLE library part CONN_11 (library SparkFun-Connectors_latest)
Multi connection point. Often used as Generic Header-pin footprint for 0.1 inch spaced/style header connections On any of the 0.1 inch spaced packages, you can populate with these: Break Away Headers - Straight (PRT-00116) Break Away Male Headers - Right Angle (PRT-00553) Female Headers (PRT-00115) Break Away Headers - Machine Pin (PRT-00117) Break Away Female Headers - Swiss Machine Pin (PRT-00743) For SCREWTERMINALS and SPRING TERMINALS visit here: Screw Terimnals on SparkFun.com (5mm/3.5mm/2.54mm spacing) This device is also useful as a general connection point to wire up your design to another part of your project. Our various solder wires solder well into these plated through hole pads. Hook-Up Wire - Assortment (Stranded, 22 AWG) (PRT-11375) Hook-Up Wire - Assortment (Solid Core, 22 AWG) (PRT-11367) View the entire wire category on our website here

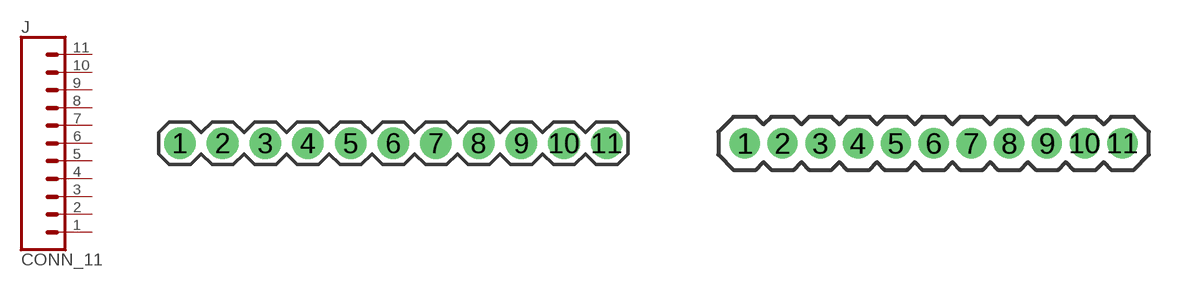
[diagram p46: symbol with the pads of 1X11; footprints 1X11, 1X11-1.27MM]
Designator prefix J

## CONN_11  [1X11]
1  1  pas
2  2  pas
3  3  pas
4  4  pas
5  5  pas
6  6  pas
7  7  pas
8  8  pas
9  9  pas
10  10  pas
11  11  pas

## CONN_11_1.27MM  [1X11-1.27MM]
Pads as for 1X11

## CONN_11LOCK  [1X11_LOCK]
Pads as for 1X11

## CONN_11LOCK_LONGPADS  [1X11_LOCK_LONGPADS]
Pads as for 1X11

## CONN_11LONGPADS  [1X11_LONGPADS]
Pads as for 1X11

## CONN_11POGOPIN_HOLES_ONLY  [1X11_HOLES_ONLY]
Pads as for 1X11

## CONN_111X11_NO_SILK  [1X11_NO_SILK]
Pads as for 1X11

## CONN_111X11_NO_SILK_KIT  [1X11_NO_SILK_KIT]
Pads as for 1X11

## Footprint 1X11 (pad centres in mm)
Plated Through Hole -11 Pin Specifications: Pin count:11 Pin pitch:0.1" Example device(s): CONN_11
drill 1.016 pad 1.88: 1 0,0; 2 2.54,0; 3 5.08,0; 4 7.62,0; 5 10.16,0; 6 12.7,0; 7 15.24,0; 8 17.78,0; 9 20.32,0; 10 22.86,0; 11 25.4,0

## Footprint 1X11-1.27MM (pad centres in mm)
Plated Through Hole -11 Pin 1.27mm Specifications: Pin count:11 Pin pitch:1.27mm Example device(s): CONN_11
drill 0.508 pad 1: 1 0,0; 2 1.27,0; 3 2.54,0; 4 3.81,0; 5 5.08,0; 6 6.35,0; 7 7.62,0; 8 8.89,0; 9 10.16,0; 10 11.43,0; 11 12.7,0

## Footprint 1X11_LOCK (pad centres in mm)
Plated Through Hole -11 Pin Locking Footprint Holes are offset 0.005" to hold pins in place while soldering. Specifications: Pin count:11 Pin pitch:0.1" Example device(s): CONN_11
drill 1.016 pad 1.88: 1 0,0.127; 2 2.54,-0.127; 3 5.08,0.127; 4 7.62,-0.127; 5 10.16,0.127; 6 12.7,-0.127; 7 15.24,0.127; 8 17.78,-0.127; 9 20.32,0.127; 10 22.86,-0.127; 11 25.4,0.127

## Footprint 1X11_LOCK_LONGPADS (pad centres in mm)
Plated Through Hole -11 Pin Locking Footprint w/ Long Pads Holes are offset 0.005" to hold pins in place while soldering. Specifications: Pin count:11 Pin pitch:0.1" Example device(s): CONN_11
drill 1.016 long: 1 0,0.127; 2 2.54,-0.127; 3 5.08,0.127; 4 7.62,-0.127; 5 10.16,0.127; 6 12.7,-0.127; 7 15.24,0.127; 8 17.78,-0.127; 9 20.32,0.127; 10 22.86,-0.127; 11 25.4,0.127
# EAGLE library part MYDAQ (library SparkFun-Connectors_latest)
myDAQ This connecotr is used in the National Instruments myDAQ measurement and control tool ecosystem. Learn more at the myDAQ website. The connector is a 20pin 3.81mm spaced Female Right Angle Terminal Block (PTH). Sorry, we do not sell the connector as an individual part at SparkFun, howere here is a link to the datasheet: Datasheet It is used on this SparkFun product: SparkFun myDAQ Protoboard Kit (DEV-10705)

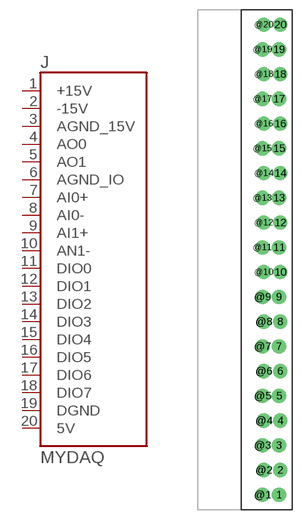
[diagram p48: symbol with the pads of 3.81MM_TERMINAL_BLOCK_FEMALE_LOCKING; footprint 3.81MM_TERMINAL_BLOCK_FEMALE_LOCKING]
Designator prefix J

## MYDAQ (PROD_ID: CONN-10450)  [3.81MM_TERMINAL_BLOCK_FEMALE_LOCKING]
1  +15V  pwr
2  -15V  pwr
3  AGND_15V  pwr
4  AO0  out
5  AO1  out
6  AGND_IO  pwr
7  AI0+  in
8  AI0-  in
9  AI1+  in
10  AN1-  in
11  DIO0
12  DIO1
13  DIO2
14  DIO3
15  DIO4
16  DIO5
17  DIO6
18  DIO7
19  DGND  pwr
20  5V  pwr

## Footprint 3.81MM_TERMINAL_BLOCK_FEMALE_LOCKING (pad centres in mm)
MyDAQ Female Right Angle Terminal Block w/ Locking Footprint Specifications: Pin count: 40 Pin pitch:3.18mm Datasheet referenced for footprint Example device(s): MyDAQ
drill 1.2 pad 2.184: 1 4.521,-36.194; 2 4.724,-32.384; 3 4.521,-28.574; 4 4.724,-24.764; 5 4.521,-20.954; 6 4.724,-17.144; 7 4.521,-13.334; 8 4.724,-9.524; 9 4.521,-5.714; 10 4.724,-1.904; 11 4.521,1.906; 12 4.724,5.716; 13 4.521,9.526; 14 4.724,13.336; 15 4.521,17.146; 16 4.724,20.956; 17 4.521,24.766; 18 4.724,28.576; 19 4.521,32.386; 20 4.724,36.196; @1 1.981,-36.194; @2 2.184,-32.384; @3 1.981,-28.574; @4 2.184,-24.764; @5 1.981,-20.954; @6 2.184,-17.144; @7 1.981,-13.334; @8 2.184,-9.524; @9 1.981,-5.714; @10 2.184,-1.904; @11 1.981,1.906; @12 2.184,5.716; @13 1.981,9.526; @14 2.184,13.336; @15 1.981,17.146; @16 2.184,20.956; @17 1.981,24.766; @18 2.184,28.576; @19 1.981,32.386; @20 2.184,36.196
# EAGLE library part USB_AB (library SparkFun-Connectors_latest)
USB Type AB Micro Connector OTG-compatible. 5 pins, 3 shield pins SparkFun Products: IOIO-OTG SparkFun SAMD21 Mini Breakout

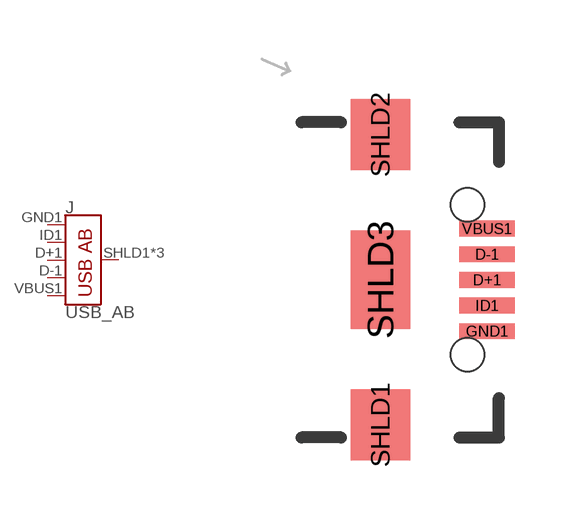
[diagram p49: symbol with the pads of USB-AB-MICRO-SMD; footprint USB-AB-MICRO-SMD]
Designator prefix J

## USB_AB_SMT (PROD_ID: CONN-11794)  [USB-AB-MICRO-SMD]
D+1  D+
D-1  D-
GND1  GND  pwr
ID1  USBID
SHLD1  SHIELD
SHLD2  SHIELD
SHLD3  SHIELD
VBUS1  VBUS  pwr

## Footprint USB-AB-MICRO-SMD (pad centres in mm)
USB Type AB - SMT Basic silk outline Specifications: Pin count:5 main, 3 shield Datasheet referenced for footprint: http://www.morethanall.com//upload/products_pdf/87340574052ba5151280ca.pdf Example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
smd 1.4 x 0.4: D+1 2.7,0; D-1 2.7,0.65; GND1 2.7,-1.3; ID1 2.7,-0.65; VBUS1 2.7,1.3
smd 1.5 x 1.8: SHLD1 0,-3.68; SHLD2 0,3.68
smd 1.5 x 2.5: SHLD3 0,0
hole 0.85 at 2.2,1.9
hole 0.85 at 2.2,-1.9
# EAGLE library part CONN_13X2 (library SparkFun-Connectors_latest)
Multi connection point. Often used as Generic Header-pin footprint for 0.1 inch spaced/style header connections On any of the 0.1 inch spaced packages, you can populate with these: Break Away Headers - Straight (PRT-00116) Break Away Male Headers - Right Angle (PRT-00553) Female Headers (PRT-00115) Break Away Headers - Machine Pin (PRT-00117) Break Away Female Headers - Swiss Machine Pin (PRT-00743)

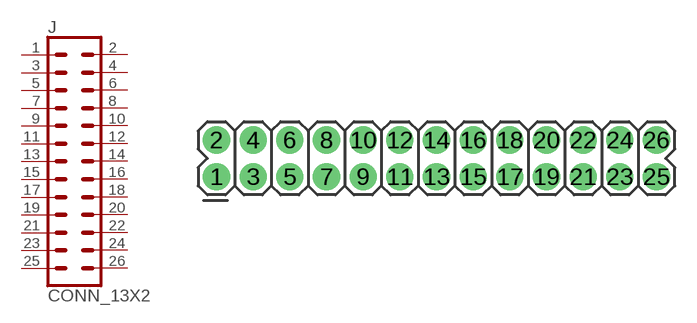
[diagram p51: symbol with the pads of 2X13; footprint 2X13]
Designator prefix J

## CONN_13X22X13  [2X13]
1  1  pas
2  2  pas
3  3  pas
4  4  pas
5  5  pas
6  6  pas
7  7  pas
8  8  pas
9  9  pas
10  10  pas
11  11  pas
12  12  pas
13  13  pas
14  14  pas
15  15  pas
16  16  pas
17  17  pas
18  18  pas
19  19  pas
20  20  pas
21  21  pas
22  22  pas
23  23  pas
24  24  pas
25  25  pas
26  26  pas

## Footprint 2X13 (pad centres in mm)
Plated Through Hole - 2x13 Specifications: Pin count:26 Pin pitch:0.1" Example device(s): CONN_13x2
drill 1.016 pad 1.88: 1 0,0; 2 0,2.54; 3 2.54,0; 4 2.54,2.54; 5 5.08,0; 6 5.08,2.54; 7 7.62,0; 8 7.62,2.54; 9 10.16,0; 10 10.16,2.54; 11 12.7,0; 12 12.7,2.54; 13 15.24,0; 14 15.24,2.54; 15 17.78,0; 16 17.78,2.54; 17 20.32,0; 18 20.32,2.54; 19 22.86,0; 20 22.86,2.54; 21 25.4,0; 22 25.4,2.54; 23 27.94,0; 24 27.94,2.54; 25 30.48,0; 26 30.48,2.54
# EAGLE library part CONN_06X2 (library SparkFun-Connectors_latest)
Multi connection point. Often used as Generic Header-pin footprint for 0.1 inch spaced/style header connections On any of the 0.1 inch spaced packages, you can populate with these: Break Away Headers - Straight (PRT-00116) Break Away Male Headers - Right Angle (PRT-00553) Female Headers (PRT-00115) Break Away Headers - Machine Pin (PRT-00117) Break Away Female Headers - Swiss Machine Pin (PRT-00743)

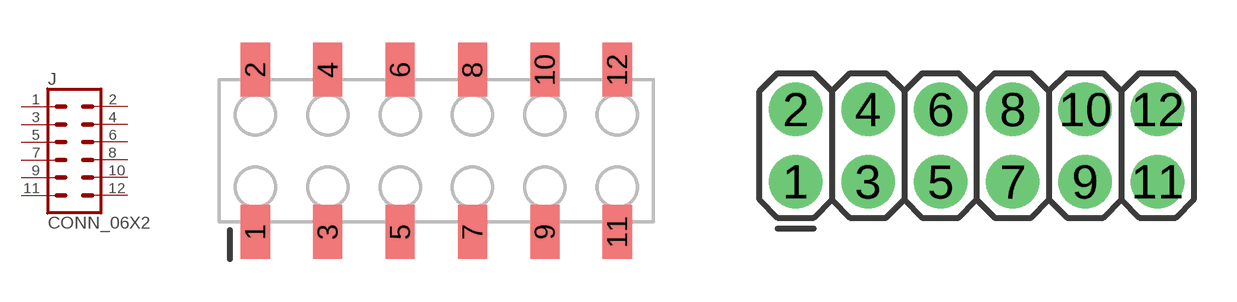
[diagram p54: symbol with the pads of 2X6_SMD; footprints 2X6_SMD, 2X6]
Designator prefix J

## CONN_06X2SMD_FEMALE  [2X6_SMD]
1  1  pas
2  2  pas
3  3  pas
4  4  pas
5  5  pas
6  6  pas
7  7  pas
8  8  pas
9  9  pas
10  10  pas
11  11  pas
12  12  pas

## CONN_06X2PTH_FEMALE (PROD_ID: CONN-12423; VALUE: 2X6 FEMALE)  [2X6]
Pads as for 2X6_SMD

## CONN_06X2NO_SILK  [2X6_NOSILK]
Pads as for 2X6_SMD

## Footprint 2X6_SMD (pad centres in mm)
Surface Mount - 2x6 Specifications: Pin count:12 Pin pitch:0.1" Example device(s): CONN_06x2
smd 1.02 x 1.9: 1 -6.35,-2.85; 2 -6.35,2.85; 3 -3.81,-2.85; 4 -3.81,2.85; 5 -1.27,-2.85; 6 -1.27,2.85; 7 1.27,-2.85; 8 1.27,2.85; 9 3.81,-2.85; 10 3.81,2.85; 11 6.35,-2.85; 12 6.35,2.85

## Footprint 2X6 (pad centres in mm)
Plated Through Hole - 2x6 Specifications: Pin count:12 Pin pitch:0.1" Example device(s): CONN_06x2
drill 1.016 pad 1.88: 1 0,0; 2 0,2.54; 3 2.54,0; 4 2.54,2.54; 5 5.08,0; 6 5.08,2.54; 7 7.62,0; 8 7.62,2.54; 9 10.16,0; 10 10.16,2.54; 11 12.7,0; 12 12.7,2.54

## Footprint 2X6_NOSILK (pad centres in mm)
drill 1.016 pad 1.88: 1 0,0; 2 0,2.54; 3 2.54,0; 4 2.54,2.54; 5 5.08,0; 6 5.08,2.54; 7 7.62,0; 8 7.62,2.54; 9 10.16,0; 10 10.16,2.54; 11 12.7,0; 12 12.7,2.54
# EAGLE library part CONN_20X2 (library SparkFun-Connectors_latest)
Multi connection point. Often used as Generic Header-pin footprint for 0.1 inch spaced/style header connections On any of the 0.1 inch spaced packages, you can populate with these: Break Away Headers - Straight (PRT-00116) Break Away Male Headers - Right Angle (PRT-00553) Female Headers (PRT-00115) Break Away Headers - Machine Pin (PRT-00117) Break Away Female Headers - Swiss Machine Pin (PRT-00743)

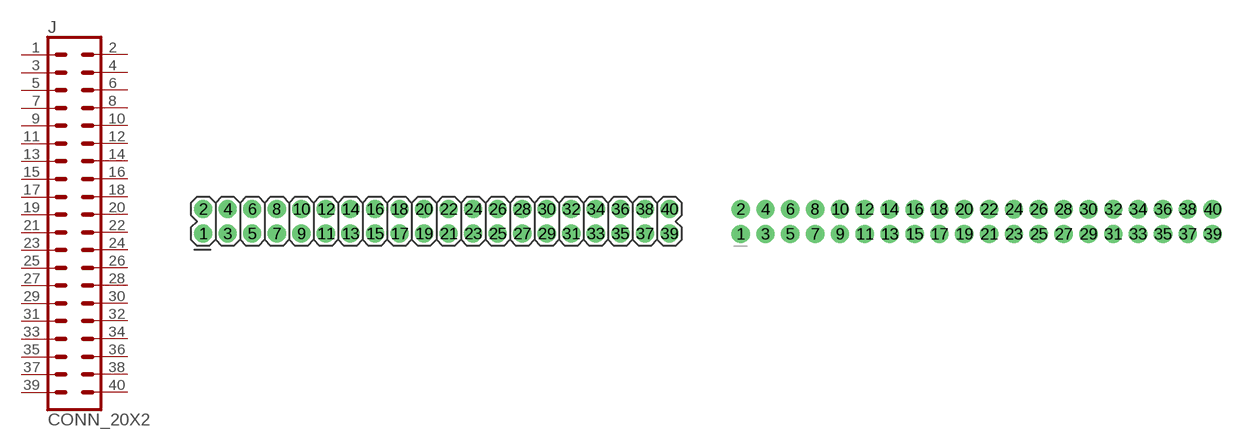
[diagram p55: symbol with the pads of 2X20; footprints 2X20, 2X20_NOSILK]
Designator prefix J

## CONN_20X2  [2X20]
1  1  pas
2  2  pas
3  3  pas
4  4  pas
5  5  pas
6  6  pas
7  7  pas
8  8  pas
9  9  pas
10  10  pas
11  11  pas
12  12  pas
13  13  pas
14  14  pas
15  15  pas
16  16  pas
17  17  pas
18  18  pas
19  19  pas
20  20  pas
21  21  pas
22  22  pas
23  23  pas
24  24  pas
25  25  pas
26  26  pas
27  27  pas
28  28  pas
29  29  pas
30  30  pas
31  31  pas
32  32  pas
33  33  pas
34  34  pas
35  35  pas
36  36  pas
37  37  pas
38  38  pas
39  39  pas
40  40  pas

## CONN_20X2NOSILK  [2X20_NOSILK]
Pads as for 2X20

## CONN_20X2SHROUDED (PROD_ID: CONN-12263; SF_ID: CONN-12263)  [2X20_SHROUDED]
Pads as for 2X20

## CONN_20X2SHROUDED_SMT (PROD_ID: CONN-13143)  [2X20_SHROUDED_SMT]
Pads as for 2X20

## Footprint 2X20 (pad centres in mm)
Plated Through Hole - 2x20 Specifications: Pin count:40 Pin pitch:0.1" Example device(s): CONN_20x2
drill 1.016 pad 1.88: 1 0,0; 2 0,2.54; 3 2.54,0; 4 2.54,2.54; 5 5.08,0; 6 5.08,2.54; 7 7.62,0; 8 7.62,2.54; 9 10.16,0; 10 10.16,2.54; 11 12.7,0; 12 12.7,2.54; 13 15.24,0; 14 15.24,2.54; 15 17.78,0; 16 17.78,2.54; 17 20.32,0; 18 20.32,2.54; 19 22.86,0; 20 22.86,2.54; 21 25.4,0; 22 25.4,2.54; 23 27.94,0; 24 27.94,2.54; 25 30.48,0; 26 30.48,2.54; 27 33.02,0; 28 33.02,2.54; 29 35.56,0; 30 35.56,2.54; 31 38.1,0; 32 38.1,2.54; 33 40.64,0; 34 40.64,2.54; 35 43.18,0; 36 43.18,2.54; 37 45.72,0; 38 45.72,2.54; 39 48.26,0; 40 48.26,2.54

## Footprint 2X20_NOSILK (pad centres in mm)
Plated Through Hole - 2x20 No Silk Outline Specifications: Pin count:40 Pin pitch:0.1" Example device(s): CONN_20x2
drill 1.016 pad 1.88: 1 0,0; 2 0,2.54; 3 2.54,0; 4 2.54,2.54; 5 5.08,0; 6 5.08,2.54; 7 7.62,0; 8 7.62,2.54; 9 10.16,0; 10 10.16,2.54; 11 12.7,0; 12 12.7,2.54; 13 15.24,0; 14 15.24,2.54; 15 17.78,0; 16 17.78,2.54; 17 20.32,0; 18 20.32,2.54; 19 22.86,0; 20 22.86,2.54; 21 25.4,0; 22 25.4,2.54; 23 27.94,0; 24 27.94,2.54; 25 30.48,0; 26 30.48,2.54; 27 33.02,0; 28 33.02,2.54; 29 35.56,0; 30 35.56,2.54; 31 38.1,0; 32 38.1,2.54; 33 40.64,0; 34 40.64,2.54; 35 43.18,0; 36 43.18,2.54; 37 45.72,0; 38 45.72,2.54; 39 48.26,0; 40 48.26,2.54

## Footprint 2X20_SHROUDED (pad centres in mm)
Plated Through Hole - 2x20 Shrouded Header Specifications: Pin count:40 Pin pitch:0.1" Datasheet referenced for footprint Example device(s): CONN_20x2
drill 1.016 pad 1.88: 1 -1.27,24.13; 2 1.27,24.13; 3 -1.27,21.59; 4 1.27,21.59; 5 -1.27,19.05; 6 1.27,19.05; 7 -1.27,16.51; 8 1.27,16.51; 9 -1.27,13.97; 10 1.27,13.97; 11 -1.27,11.43; 12 1.27,11.43; 13 -1.27,8.89; 14 1.27,8.89; 15 -1.27,6.35; 16 1.27,6.35; 17 -1.27,3.81; 18 1.27,3.81; 19 -1.27,1.27; 20 1.27,1.27; 21 -1.27,-1.27; 22 1.27,-1.27; 23 -1.27,-3.81; 24 1.27,-3.81; 25 -1.27,-6.35; 26 1.27,-6.35; 27 -1.27,-8.89; 28 1.27,-8.89; 29 -1.27,-11.43; 30 1.27,-11.43; 31 -1.27,-13.97; 32 1.27,-13.97; 33 -1.27,-16.51; 34 1.27,-16.51; 35 -1.27,-19.05; 36 1.27,-19.05; 37 -1.27,-21.59; 38 1.27,-21.59; 39 -1.27,-24.13; 40 1.27,-24.13

## Footprint 2X20_SHROUDED_SMT (pad centres in mm)
Surface Mount - 2x20 Shrouded Header Specifications: Pin count:40 Pin pitch:0.1" Datasheet referenced for footprint Example device(s): CONN_20x2
smd 4.14 x 0.991: 1 -3.569,24.13; 2 3.569,24.13; 3 -3.569,21.59; 4 3.569,21.59; 5 -3.569,19.05; 6 3.569,19.05; 7 -3.569,16.51; 8 3.569,16.51; 9 -3.569,13.97; 10 3.569,13.97; 11 -3.569,11.43; 12 3.569,11.43; 13 -3.569,8.89; 14 3.569,8.89; 15 -3.569,6.35; 16 3.569,6.35; 17 -3.569,3.81; 18 3.569,3.81; 19 -3.569,1.27; 20 3.569,1.27; 21 -3.569,-1.27; 22 3.569,-1.27; 23 -3.569,-3.81; 24 3.569,-3.81; 25 -3.569,-6.35; 26 3.569,-6.35; 27 -3.569,-8.89; 28 3.569,-8.89; 29 -3.569,-11.43; 30 3.569,-11.43; 31 -3.569,-13.97; 32 3.569,-13.97; 33 -3.569,-16.51; 34 3.569,-16.51; 35 -3.569,-19.05; 36 3.569,-19.05; 37 -3.569,-21.59; 38 3.569,-21.59; 39 -3.569,-24.13; 40 3.569,-24.13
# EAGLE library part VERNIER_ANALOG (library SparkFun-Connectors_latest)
British Telecom Connector - BTA (female) This device is useful when designing a project that uses any of the analog sensors in the Vernier ecosystem (sensors and/or controllers) SparkFun Products: SparkFun Vernier Interface Shield (DEV-12858) British Telecom Connector - BTA (female)

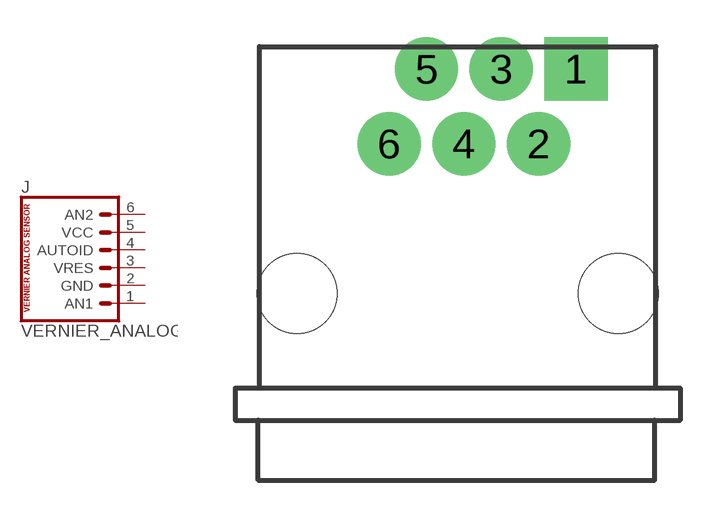
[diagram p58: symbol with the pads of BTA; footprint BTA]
Designator prefix J

## VERNIER_ANALOG (PROD_ID: CONN-11653; SF_ID: PRT-12753)  [BTA]
1  AN1  pas
2  GND  pas
3  VRES  pas
4  AUTOID  pas
5  VCC  pas
6  AN2  pas

## Footprint BTA (pad centres in mm)
British Telecom Connector - Analog Right Angle Specifications: Pin count: 6 Datasheet referenced for footprint Example device(s): VERNIER_ANALOG
drill 1.4 pad 2.54 square: 1 4.75,9
drill 1.4 pad 2.54: 2 3.25,6; 3 1.75,9; 4 0.25,6; 5 -1.25,9; 6 -2.75,6
hole 3.2 at 6.45,0
hole 3.2 at -6.45,0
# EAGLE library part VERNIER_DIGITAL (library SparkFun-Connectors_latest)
British Telecom Connector - BTD Digital (female) This device is useful when designing a project that uses any of the analog sensors in the Vernier ecosystem (sensors and/or controllers) SparkFun Products: SparkFun Vernier Interface Shield (DEV-12858) British Telecom Connector - BTD (female) More information about the Vernier ecosystem can be found here: http://www.vernier.com/engineering/arduino/

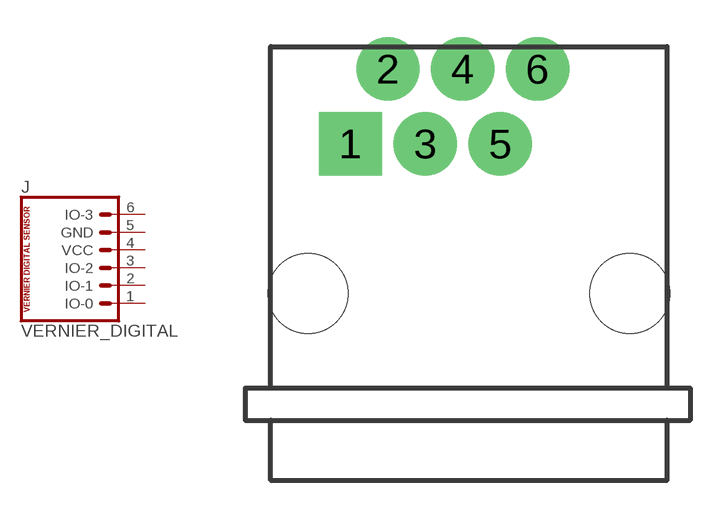
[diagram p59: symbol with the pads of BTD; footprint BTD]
Designator prefix J

## VERNIER_DIGITAL (PROD_ID: CONN-11654; SF_ID: PRT-12754)  [BTD]
1  IO-0  pas
2  IO-1  pas
3  IO-2  pas
4  VCC  pas
5  GND  pas
6  IO-3  pas

## Footprint BTD (pad centres in mm)
British Telecom Connector - Right Angle Female Digital Specifications: Pin count: 6 Datasheet referenced for footprint Example device(s): VERNIER_DIGITAL
drill 1.4 pad 2.54 square: 1 -4.75,6
drill 1.4 pad 2.54: 2 -3.25,9; 3 -1.75,6; 4 -0.25,9; 5 1.25,6; 6 2.75,9
hole 3.2 at 6.45,0
hole 3.2 at -6.45,0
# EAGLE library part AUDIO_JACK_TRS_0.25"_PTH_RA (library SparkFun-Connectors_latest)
Audio Jack, 1/4" TRS jack, horizontal, PTH, aka "Phono jack" Find the connector here: Audio Jack - 1/4" Stereo (right angle) (COM-11144) Datasheet Note, although the datasheet and physical part are slightly different, this footprint was proven to mate well on the Proto Pedal. This device is used on these SparkFun Products: SparkFun TRS Jack Breakout - 1/4" Stereo (BOB-13005 ) SparkFun Proto Pedal - sorry bad link - product comming soon! (PRT-13124)

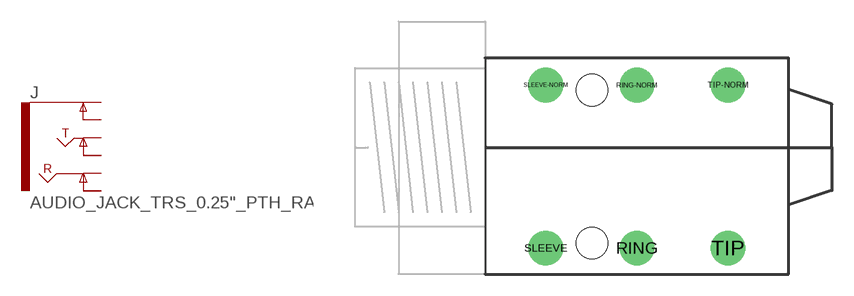
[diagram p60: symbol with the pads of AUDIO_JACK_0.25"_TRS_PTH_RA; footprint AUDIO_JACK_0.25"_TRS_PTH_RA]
Designator prefix J

## AUDIO_JACK_TRS_0.25"_PTH_RA (PROD_ID: CONN-12339; SF_ID: COM-11144)  [AUDIO_JACK_0.25"_TRS_PTH_RA]
RING  RING
RING-NORM  RING-NORM
SLEEVE  EARTH
SLEEVE-NORM  EARTH-NORM
TIP  TIP
TIP-NORM  TIP-NORM

## Footprint AUDIO_JACK_0.25"_TRS_PTH_RA (pad centres in mm)
Right Angle -1/4" Stereo Jack Specifications: Pin count: 6 Datasheet referenced for footprint Example device(s): AUDIO_JACK_TRS_0.25"_PTH_RA
drill 1.6: RING 10.5,-6.95; RING-NORM 10.5,4.35; SLEEVE 4.2,-6.95; SLEEVE-NORM 4.2,4.35; TIP 16.8,-6.95; TIP-NORM 16.8,4.35
hole 2.2 at 7.4,4
hole 2.2 at 7.4,-6.6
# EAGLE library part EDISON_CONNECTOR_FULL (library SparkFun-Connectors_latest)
Intel &reg; Edison Hirose Connectors DF40 Series 70 pin connector 3mm headers and sockets used on the SparkFun Edison Blocks. Edison Daughter package includes layout for the Edison module itself, including mounting holes and antenna area marked. SparkFun Products: SparkFun ADC Edison Block SparkFun Power Edison Block SparkFun Base Edison Block SparkFun Dual H-Bridge Edison Block SparkFun microSD Edison Block

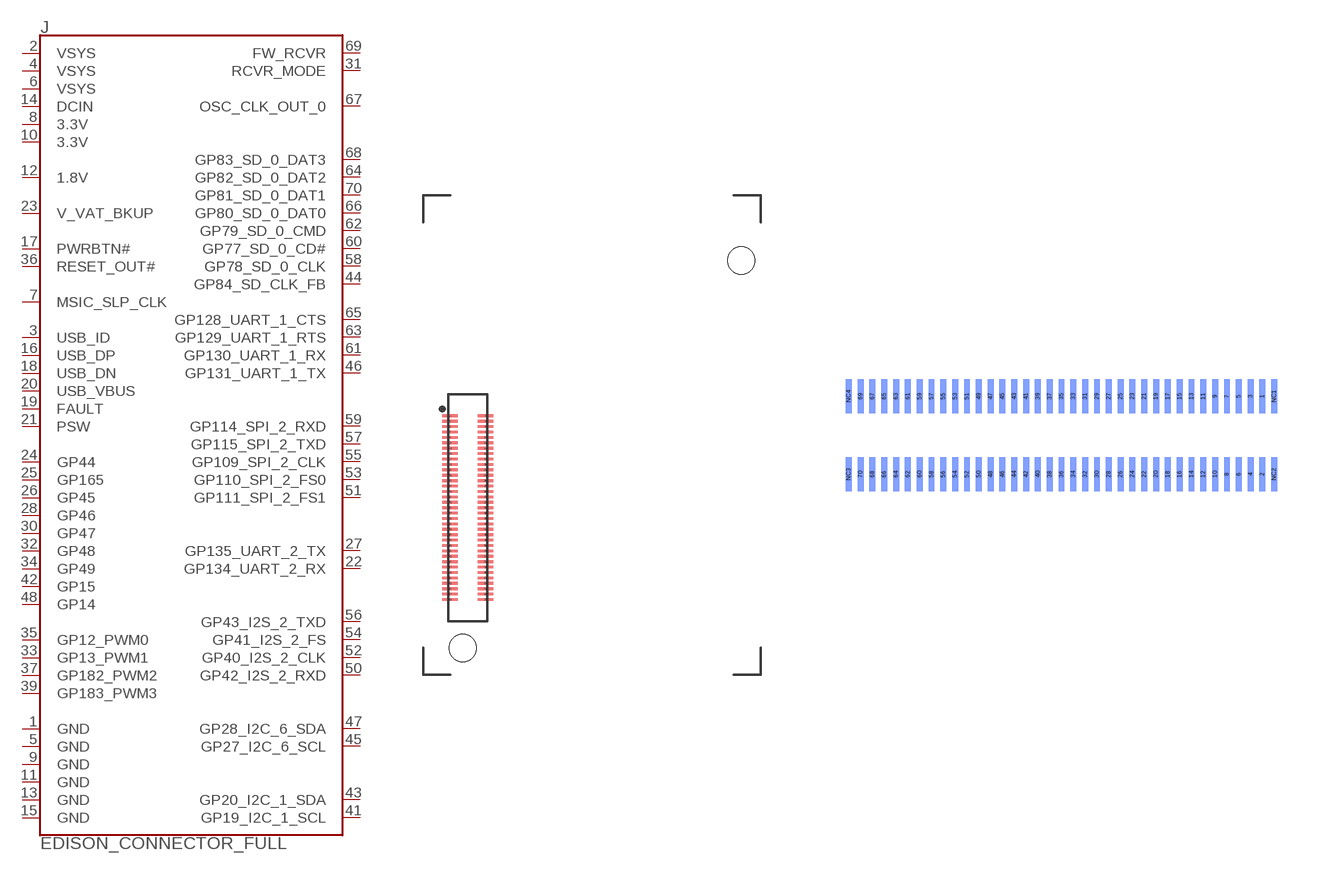
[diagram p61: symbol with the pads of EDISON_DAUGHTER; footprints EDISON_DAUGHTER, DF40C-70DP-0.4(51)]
Designator prefix J

## EDISON_CONNECTOR_FULL_MOUNTING_HOLES  [EDISON_DAUGHTER]
1  GND
2  VSYS
3  USB_ID
4  VSYS
5  GND
6  VSYS
7  MSIC_SLP_CLK
8  3.3V
9  GND
10  3.3V
11  GND
12  1.8V
13  GND
14  DCIN
15  GND
16  USB_DP
17  PWRBTN#
18  USB_DN
19  FAULT
20  USB_VBUS
21  PSW
22  GP134_UART_2_RX
23  V_VAT_BKUP
24  GP44
25  GP165
26  GP45
27  GP135_UART_2_TX
28  GP46
30  GP47
31  RCVR_MODE
32  GP48
33  GP13_PWM1
34  GP49
35  GP12_PWM0
36  RESET_OUT#
37  GP182_PWM2
39  GP183_PWM3
41  GP19_I2C_1_SCL
42  GP15
43  GP20_I2C_1_SDA
44  GP84_SD_CLK_FB
45  GP27_I2C_6_SCL
46  GP131_UART_1_TX
47  GP28_I2C_6_SDA
48  GP14
50  GP42_I2S_2_RXD
51  GP111_SPI_2_FS1
52  GP40_I2S_2_CLK
53  GP110_SPI_2_FS0
54  GP41_I2S_2_FS
55  GP109_SPI_2_CLK
56  GP43_I2S_2_TXD
57  GP115_SPI_2_TXD
58  GP78_SD_0_CLK
59  GP114_SPI_2_RXD
60  GP77_SD_0_CD#
61  GP130_UART_1_RX
62  GP79_SD_0_CMD
63  GP129_UART_1_RTS
64  GP82_SD_0_DAT2
65  GP128_UART_1_CTS
66  GP80_SD_0_DAT0
67  OSC_CLK_OUT_0
68  GP83_SD_0_DAT3
69  FW_RCVR
70  GP81_SD_0_DAT1

## EDISON_CONNECTOR_FULL_HEADER (PROD_ID: CONN-12248)  [DF40C-70DP-0.4(51)]
Pads as for EDISON_DAUGHTER

## EDISON_CONNECTOR_FULL_SOCKET (PROD_ID: CONN-12247)  [DF40-XC-(X.X)-70DS-0.4V(51)]
Pads as for EDISON_DAUGHTER

## Footprint EDISON_DAUGHTER (pad centres in mm)
Hirose DF30C-70DP-0.4V(51) Receiver Footprint w/ Edison Outline Package can be used as basic guideline for creating Edison-mating daughter boards. Includes keepout area for antenna. Specifications: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
smd 1.14 x 0.2: 1 1.98,19.17; 2 4.62,19.17; 3 1.98,18.77; 4 4.62,18.77; 5 1.98,18.37; 6 4.62,18.37; 7 1.98,17.97; 8 4.62,17.97; 9 1.98,17.57; 10 4.62,17.57; 11 1.98,17.17; 12 4.62,17.17; 13 1.98,16.77; 14 4.62,16.77; 15 1.98,16.37; 16 4.62,16.37; 17 1.98,15.97; 18 4.62,15.97; 19 1.98,15.57; 20 4.62,15.57; 21 1.98,15.17; 22 4.62,15.17; 23 1.98,14.77; 24 4.62,14.77; 25 1.98,14.37; 26 4.62,14.37; 27 1.98,13.97; 28 4.62,13.97; 29 1.98,13.57; 30 4.62,13.57; 31 1.98,13.17; 32 4.62,13.17; 33 1.98,12.77; 34 4.62,12.77; 35 1.98,12.37; 36 4.62,12.37; 37 1.98,11.97; 38 4.62,11.97; 39 1.98,11.57; 40 4.62,11.57; 41 1.98,11.17; 42 4.62,11.17; 43 1.98,10.77; 44 4.62,10.77; 45 1.98,10.37; 46 4.62,10.37; 47 1.98,9.97; 48 4.62,9.97; 49 1.98,9.57; 50 4.62,9.57; 51 1.98,9.17; 52 4.62,9.17; 53 1.98,8.77; 54 4.62,8.77; 55 1.98,8.37; 56 4.62,8.37; 57 1.98,7.97; 58 4.62,7.97; 59 1.98,7.57; 60 4.62,7.57; 61 1.98,7.17; 62 4.62,7.17; 63 1.98,6.77; 64 4.62,6.77; 65 1.98,6.37; 66 4.62,6.37; 67 1.98,5.97; 68 4.62,5.97; 69 1.98,5.57; 70 4.62,5.57
hole 2 at 23.53,30.67
hole 2 at 2.93,1.98

## Footprint DF40C-70DP-0.4(51) (pad centres in mm)
Hirose DF30C-70DP-0.4V(51) Receiver Specifications: Pin count:70 Pin pitch: 0.4mm Datasheet referenced for footprint Example device(s): EDISON_FULL_CONNECTOR
smd 0.2 x 1.14 bottom: 1 6.8,1.32; 2 6.8,-1.32; 3 6.4,1.32; 4 6.4,-1.32; 5 6,1.32; 6 6,-1.32; 7 5.6,1.32; 8 5.6,-1.32; 9 5.2,1.32; 10 5.2,-1.32; 11 4.8,1.32; 12 4.8,-1.32; 13 4.4,1.32; 14 4.4,-1.32; 15 4,1.32; 16 4,-1.32; 17 3.6,1.32; 18 3.6,-1.32; 19 3.2,1.32; 20 3.2,-1.32; 21 2.8,1.32; 22 2.8,-1.32; 23 2.4,1.32; 24 2.4,-1.32; 25 2,1.32; 26 2,-1.32; 27 1.6,1.32; 28 1.6,-1.32; 29 1.2,1.32; 30 1.2,-1.32; 31 0.8,1.32; 32 0.8,-1.32; 33 0.4,1.32; 34 0.4,-1.32; 35 0,1.32; 36 0,-1.32; 37 -0.4,1.32; 38 -0.4,-1.32; 39 -0.8,1.32; 40 -0.8,-1.32; 41 -1.2,1.32; 42 -1.2,-1.32; 43 -1.6,1.32; 44 -1.6,-1.32; 45 -2,1.32; 46 -2,-1.32; 47 -2.4,1.32; 48 -2.4,-1.32; 49 -2.8,1.32; 50 -2.8,-1.32; 51 -3.2,1.32; 52 -3.2,-1.32; 53 -3.6,1.32; 54 -3.6,-1.32; 55 -4,1.32; 56 -4,-1.32; 57 -4.4,1.32; 58 -4.4,-1.32; 59 -4.8,1.32; 60 -4.8,-1.32; 61 -5.2,1.32; 62 -5.2,-1.32; 63 -5.6,1.32; 64 -5.6,-1.32; 65 -6,1.32; 66 -6,-1.32; 67 -6.4,1.32; 68 -6.4,-1.32; 69 -6.8,1.32; 70 -6.8,-1.32; NC1 7.2,1.32; NC2 7.2,-1.32; NC3 -7.2,-1.32; NC4 -7.2,1.32

## Footprint DF40-XC-(X.X)-70DS-0.4V(51) (pad centres in mm)
Hirose DF40C-70DP-0.4V(51) Plug Specifications: Pin count:70 Pin pitch: 0.4mm Datasheet referenced for footprint Example device(s): EDISON_FULL_CONNECTOR
smd 0.2 x 1.14: 1 6.8,1.32; 2 6.8,-1.32; 3 6.4,1.32; 4 6.4,-1.32; 5 6,1.32; 6 6,-1.32; 7 5.6,1.32; 8 5.6,-1.32; 9 5.2,1.32; 10 5.2,-1.32; 11 4.8,1.32; 12 4.8,-1.32; 13 4.4,1.32; 14 4.4,-1.32; 15 4,1.32; 16 4,-1.32; 17 3.6,1.32; 18 3.6,-1.32; 19 3.2,1.32; 20 3.2,-1.32; 21 2.8,1.32; 22 2.8,-1.32; 23 2.4,1.32; 24 2.4,-1.32; 25 2,1.32; 26 2,-1.32; 27 1.6,1.32; 28 1.6,-1.32; 29 1.2,1.32; 30 1.2,-1.32; 31 0.8,1.32; 32 0.8,-1.32; 33 0.4,1.32; 34 0.4,-1.32; 35 0,1.32; 36 0,-1.32; 37 -0.4,1.32; 38 -0.4,-1.32; 39 -0.8,1.32; 40 -0.8,-1.32; 41 -1.2,1.32; 42 -1.2,-1.32; 43 -1.6,1.32; 44 -1.6,-1.32; 45 -2,1.32; 46 -2,-1.32; 47 -2.4,1.32; 48 -2.4,-1.32; 49 -2.8,1.32; 50 -2.8,-1.32; 51 -3.2,1.32; 52 -3.2,-1.32; 53 -3.6,1.32; 54 -3.6,-1.32; 55 -4,1.32; 56 -4,-1.32; 57 -4.4,1.32; 58 -4.4,-1.32; 59 -4.8,1.32; 60 -4.8,-1.32; 61 -5.2,1.32; 62 -5.2,-1.32; 63 -5.6,1.32; 64 -5.6,-1.32; 65 -6,1.32; 66 -6,-1.32; 67 -6.4,1.32; 68 -6.4,-1.32; 69 -6.8,1.32; 70 -6.8,-1.32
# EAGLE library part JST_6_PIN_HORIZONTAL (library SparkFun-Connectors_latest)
JST 6 pin horizontal connector JST-SH type. Here is the connector we sell at SparkFun: name (XXX-00000) Datasheet It was used on these SparkFun products: name (XXX-00000) name (XXX-00000)

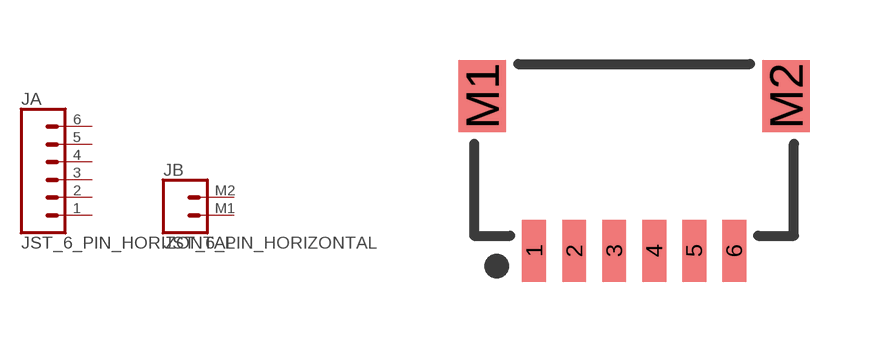
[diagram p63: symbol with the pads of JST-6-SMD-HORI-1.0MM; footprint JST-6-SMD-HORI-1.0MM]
Designator prefix J; gates A=CONN_06 B=CONN_02

## JST_6_PIN_HORIZONTAL (PROD_ID: XXX-00000; VALUE: BM06B-SRSS-TB)  [JST-6-SMD-HORI-1.0MM]
1  A:1  pas
2  A:2  pas
3  A:3  pas
4  A:4  pas
5  A:5  pas
6  A:6  pas
M1  B:1  pas
M2  B:2  pas

## Footprint JST-6-SMD-HORI-1.0MM (pad centres in mm)
JST SH Vertical 6-Pin SMT Specifications: Pin count:6 Pin pitch: 1 mm Datasheet referenced for footprint Example device(s): JST_6PIN_VERTICAL
smd 0.6 x 1.55: 1 -2.5,-4.775; 2 -1.5,-4.775; 3 -0.5,-4.775; 4 0.5,-4.775; 5 1.5,-4.775; 6 2.5,-4.775
smd 1.2 x 1.8: M1 -3.8,-0.9; M2 3.8,-0.9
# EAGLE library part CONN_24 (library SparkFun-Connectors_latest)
Multi connection point. Often used as Generic Header-pin footprint for 0.1 inch spaced/style header connections On any of the 0.1 inch spaced packages, you can populate with these: Break Away Headers - Straight (PRT-00116) Break Away Male Headers - Right Angle (PRT-00553) Female Headers (PRT-00115) Break Away Headers - Machine Pin (PRT-00117) Break Away Female Headers - Swiss Machine Pin (PRT-00743) For SCREWTERMINALS and SPRING TERMINALS visit here: Screw Terimnals on SparkFun.com (5mm/3.5mm/2.54mm spacing) This device is also useful as a general connection point to wire up your design to another part of your project. Our various solder wires solder well into these plated through hole pads. Hook-Up Wire - Assortment (Stranded, 22 AWG) (PRT-11375) Hook-Up Wire - Assortment (Solid Core, 22 AWG) (PRT-11367) View the entire wire category on our website here Special notes: Molex polarized connector foot print use with SKU : PRT-08231 with associated crimp pins and housings. 1MM SMD Version SKU: PRT-10208 NOTES ON THE VARIANTS LOCK and LOCK_LONGPADS... This footprint was designed to help hold the alignment of a through-hole component (i.e. 6-pin header) while soldering it into place. You may notice that each hole has been shifted either up or down by 0.005 of an inch from it's more standard position (which is a perfectly straight line). This slight alteration caused the pins (the squares in the middle) to touch the edges of the holes. Because they are alternating, it causes a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

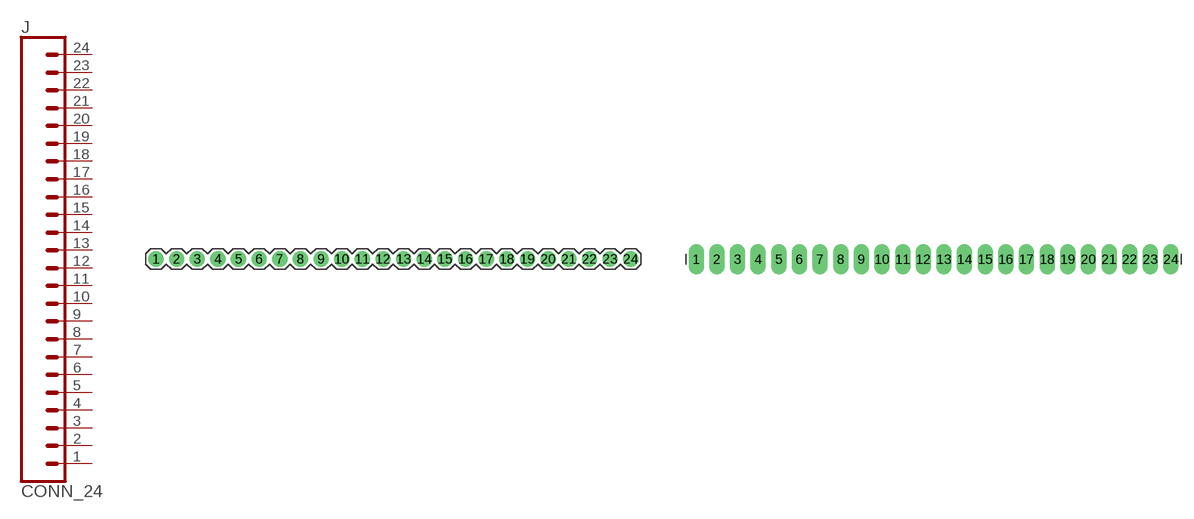
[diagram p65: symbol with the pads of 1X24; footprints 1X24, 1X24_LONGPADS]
Designator prefix J

## CONN_24  [1X24]
1  1  pas
2  2  pas
3  3  pas
4  4  pas
5  5  pas
6  6  pas
7  7  pas
8  8  pas
9  9  pas
10  10  pas
11  11  pas
12  12  pas
13  13  pas
14  14  pas
15  15  pas
16  16  pas
17  17  pas
18  18  pas
19  19  pas
20  20  pas
21  21  pas
22  22  pas
23  23  pas
24  24  pas

## CONN_24LONGPADS  [1X24_LONGPADS]
Pads as for 1X24

## CONN_24LOCK  [1X24_LOCK]
Pads as for 1X24

## Footprint 1X24 (pad centres in mm)
Plated Through Hole -24 Pin Specifications: Pin count:24 Pin pitch:0.1" Example device(s): CONN_24
drill 1.016 pad 1.88: 1 -26.67,0; 2 -24.13,0; 3 -21.59,0; 4 -19.05,0; 5 -16.51,0; 6 -13.97,0; 7 -11.43,0; 8 -8.89,0; 9 -6.35,0; 10 -3.81,0; 11 -1.27,0; 12 1.27,0; 13 3.81,0; 14 6.35,0; 15 8.89,0; 16 11.43,0; 17 13.97,0; 18 16.51,0; 19 19.05,0; 20 21.59,0; 21 24.13,0; 22 26.67,0; 23 29.21,0; 24 31.75,0

## Footprint 1X24_LONGPADS (pad centres in mm)
Plated Through Hole -24 Pin Long Pads Specifications: Pin count:24 Pin pitch:0.1" Example device(s): CONN_24
drill 1.118 pad 1.88 long: 1 -26.67,0; 2 -24.13,0; 3 -21.59,0; 4 -19.05,0; 5 -16.51,0; 6 -13.97,0; 7 -11.43,0; 8 -8.89,0; 9 -6.35,0; 10 -3.81,0; 11 -1.27,0; 12 1.27,0; 13 3.81,0; 14 6.35,0; 15 8.89,0; 16 11.43,0; 17 13.97,0; 18 16.51,0; 19 19.05,0; 20 21.59,0; 21 24.13,0; 22 26.67,0; 23 29.21,0; 24 31.75,0

## Footprint 1X24_LOCK (pad centres in mm)
Plated Through Hole -24 Pin Locking Footprint Holes are offset 0.005" from center, to hold pins in place while soldering. Specifications: Pin count:24 Pin pitch:0.1" Example device(s): CONN_24
drill 1.016 pad 1.88: 1 -26.67,-0.127; 2 -24.13,0.127; 3 -21.59,-0.127; 4 -19.05,0.127; 5 -16.51,-0.127; 6 -13.97,0.127; 7 -11.43,-0.127; 8 -8.89,0.127; 9 -6.35,-0.127; 10 -3.81,0.127; 11 -1.27,-0.127; 12 1.27,0.127; 13 3.81,-0.127; 14 6.35,0.127; 15 8.89,-0.127; 16 11.43,0.127; 17 13.97,-0.127; 18 16.51,0.127; 19 19.05,-0.127; 20 21.59,0.127; 21 24.13,-0.127; 22 26.67,0.127; 23 29.21,-0.127; 24 31.75,0.127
